##
## LEF for PtnCells ;
## created by Innovus v15.23-s045_1 on Sun Mar 16 13:41:42 2025
##

VERSION 5.8 ;

BUSBITCHARS "[]" ;
DIVIDERCHAR "/" ;

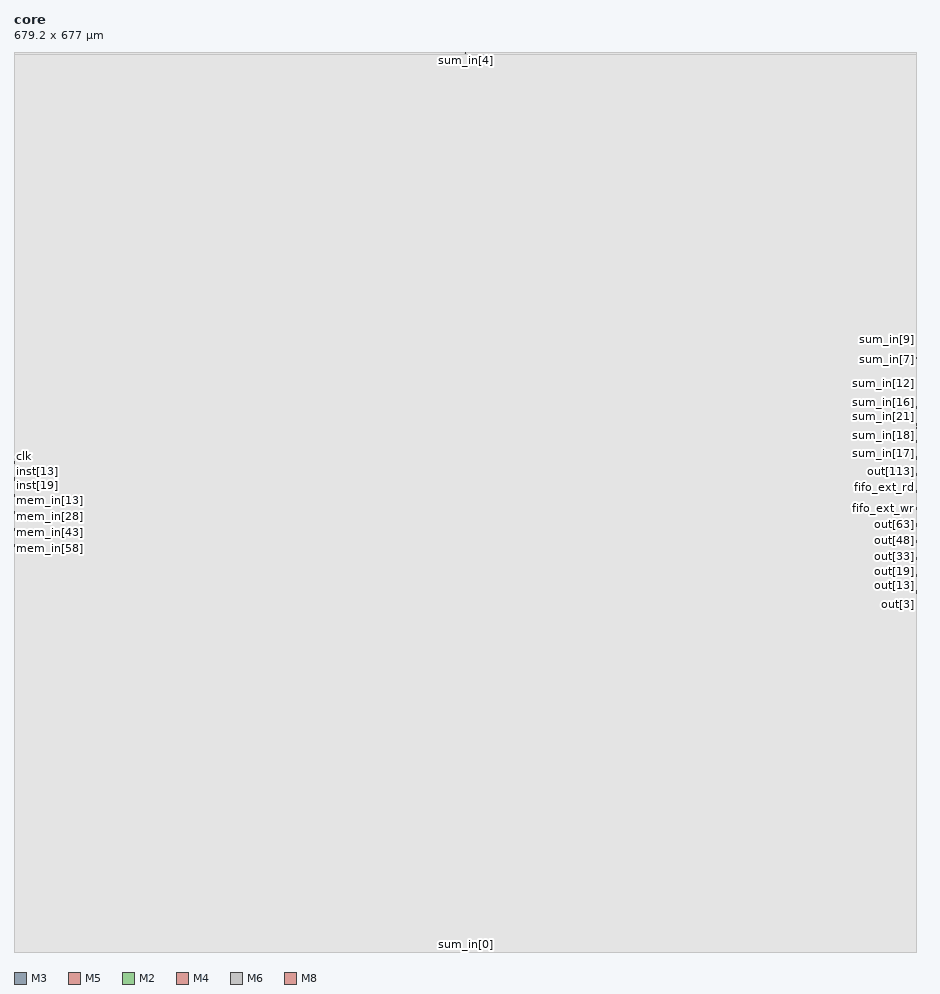
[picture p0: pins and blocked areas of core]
MACRO core
  CLASS BLOCK ;
  SIZE 679.2000 BY 677.0000 ;
  FOREIGN core 0.0000 0.0000 ;
  ORIGIN 0 0 ;
  SYMMETRY X Y R90 ;
  PIN clk
    DIRECTION INPUT ;
    USE SIGNAL ;
    PORT
      LAYER M3 ;
        RECT 0.0000 372.5500 0.6000 372.6500 ;
    END
  END clk
  PIN fifo_ext_rd
    DIRECTION OUTPUT ;
    USE SIGNAL ;
    PORT
      LAYER M5 ;
        RECT 678.6800 349.3500 679.2000 349.4500 ;
    END
  END fifo_ext_rd
  PIN fifo_ext_wr
    DIRECTION OUTPUT ;
    USE SIGNAL ;
    PORT
      LAYER M5 ;
        RECT 678.6800 339.7500 679.2000 339.8500 ;
    END
  END fifo_ext_wr
  PIN sum_in[23]
    DIRECTION INPUT ;
    USE SIGNAL ;
    PORT
      LAYER M5 ;
        RECT 678.6800 383.7500 679.2000 383.8500 ;
    END
  END sum_in[23]
  PIN sum_in[22]
    DIRECTION INPUT ;
    USE SIGNAL ;
    PORT
      LAYER M5 ;
        RECT 678.6800 401.3500 679.2000 401.4500 ;
    END
  END sum_in[22]
  PIN sum_in[21]
    DIRECTION INPUT ;
    USE SIGNAL ;
    PORT
      LAYER M5 ;
        RECT 678.6800 408.5500 679.2000 408.6500 ;
    END
  END sum_in[21]
  PIN sum_in[20]
    DIRECTION INPUT ;
    USE SIGNAL ;
    PORT
      LAYER M3 ;
        RECT 678.6800 399.9500 679.2000 400.0500 ;
    END
  END sum_in[20]
  PIN sum_in[19]
    DIRECTION INPUT ;
    USE SIGNAL ;
    PORT
      LAYER M5 ;
        RECT 678.6800 396.9500 679.2000 397.0500 ;
    END
  END sum_in[19]
  PIN sum_in[18]
    DIRECTION INPUT ;
    USE SIGNAL ;
    PORT
      LAYER M5 ;
        RECT 678.6800 394.1500 679.2000 394.2500 ;
    END
  END sum_in[18]
  PIN sum_in[17]
    DIRECTION INPUT ;
    USE SIGNAL ;
    PORT
      LAYER M3 ;
        RECT 678.6800 375.1500 679.2000 375.2500 ;
    END
  END sum_in[17]
  PIN sum_in[16]
    DIRECTION INPUT ;
    USE SIGNAL ;
    PORT
      LAYER M3 ;
        RECT 678.6800 413.3500 679.2000 413.4500 ;
    END
  END sum_in[16]
  PIN sum_in[15]
    DIRECTION INPUT ;
    USE SIGNAL ;
    PORT
      LAYER M3 ;
        RECT 678.6800 417.7500 679.2000 417.8500 ;
    END
  END sum_in[15]
  PIN sum_in[14]
    DIRECTION INPUT ;
    USE SIGNAL ;
    PORT
      LAYER M3 ;
        RECT 678.6800 433.7500 679.2000 433.8500 ;
    END
  END sum_in[14]
  PIN sum_in[13]
    DIRECTION INPUT ;
    USE SIGNAL ;
    PORT
      LAYER M3 ;
        RECT 678.6800 429.3500 679.2000 429.4500 ;
    END
  END sum_in[13]
  PIN sum_in[12]
    DIRECTION INPUT ;
    USE SIGNAL ;
    PORT
      LAYER M3 ;
        RECT 678.6800 427.5500 679.2000 427.6500 ;
    END
  END sum_in[12]
  PIN sum_in[11]
    DIRECTION INPUT ;
    USE SIGNAL ;
    PORT
      LAYER M3 ;
        RECT 678.6800 440.1500 679.2000 440.2500 ;
    END
  END sum_in[11]
  PIN sum_in[10]
    DIRECTION INPUT ;
    USE SIGNAL ;
    PORT
      LAYER M3 ;
        RECT 678.6800 446.7500 679.2000 446.8500 ;
    END
  END sum_in[10]
  PIN sum_in[9]
    DIRECTION INPUT ;
    USE SIGNAL ;
    PORT
      LAYER M3 ;
        RECT 678.6800 454.5500 679.2000 454.6500 ;
    END
  END sum_in[9]
  PIN sum_in[8]
    DIRECTION INPUT ;
    USE SIGNAL ;
    PORT
      LAYER M3 ;
        RECT 678.6800 459.1500 679.2000 459.2500 ;
    END
  END sum_in[8]
  PIN sum_in[7]
    DIRECTION INPUT ;
    USE SIGNAL ;
    PORT
      LAYER M3 ;
        RECT 678.6800 445.3500 679.2000 445.4500 ;
    END
  END sum_in[7]
  PIN sum_in[6]
    DIRECTION INPUT ;
    USE SIGNAL ;
    PORT
      LAYER M2 ;
        RECT 339.6500 676.4800 339.7500 677.0000 ;
    END
  END sum_in[6]
  PIN sum_in[5]
    DIRECTION INPUT ;
    USE SIGNAL ;
    PORT
      LAYER M4 ;
        RECT 339.6500 676.4800 339.7500 677.0000 ;
    END
  END sum_in[5]
  PIN sum_in[4]
    DIRECTION INPUT ;
    USE SIGNAL ;
    PORT
      LAYER M6 ;
        RECT 339.6500 676.4800 339.7500 677.0000 ;
    END
  END sum_in[4]
  PIN sum_in[3]
    DIRECTION INPUT ;
    USE SIGNAL ;
    PORT
      LAYER M8 ;
        RECT 339.5000 675.5850 339.9000 677.0000 ;
    END
  END sum_in[3]
  PIN sum_in[2]
    DIRECTION INPUT ;
    USE SIGNAL ;
    PORT
      LAYER M2 ;
        RECT 339.6500 0.0000 339.7500 0.5200 ;
    END
  END sum_in[2]
  PIN sum_in[1]
    DIRECTION INPUT ;
    USE SIGNAL ;
    PORT
      LAYER M4 ;
        RECT 339.6500 0.0000 339.7500 0.5200 ;
    END
  END sum_in[1]
  PIN sum_in[0]
    DIRECTION INPUT ;
    USE SIGNAL ;
    PORT
      LAYER M6 ;
        RECT 339.6500 0.0000 339.7500 0.5200 ;
    END
  END sum_in[0]
  PIN sum_out[23]
    DIRECTION OUTPUT ;
    USE SIGNAL ;
    PORT
      LAYER M3 ;
        RECT 678.6000 411.5500 679.2000 411.6500 ;
    END
  END sum_out[23]
  PIN sum_out[22]
    DIRECTION OUTPUT ;
    USE SIGNAL ;
    PORT
      LAYER M3 ;
        RECT 678.6000 410.7500 679.2000 410.8500 ;
    END
  END sum_out[22]
  PIN sum_out[21]
    DIRECTION OUTPUT ;
    USE SIGNAL ;
    PORT
      LAYER M3 ;
        RECT 678.6000 409.9500 679.2000 410.0500 ;
    END
  END sum_out[21]
  PIN sum_out[20]
    DIRECTION OUTPUT ;
    USE SIGNAL ;
    PORT
      LAYER M3 ;
        RECT 678.6000 409.1500 679.2000 409.2500 ;
    END
  END sum_out[20]
  PIN sum_out[19]
    DIRECTION OUTPUT ;
    USE SIGNAL ;
    PORT
      LAYER M3 ;
        RECT 678.6000 408.3500 679.2000 408.4500 ;
    END
  END sum_out[19]
  PIN sum_out[18]
    DIRECTION OUTPUT ;
    USE SIGNAL ;
    PORT
      LAYER M3 ;
        RECT 678.6000 407.5500 679.2000 407.6500 ;
    END
  END sum_out[18]
  PIN sum_out[17]
    DIRECTION OUTPUT ;
    USE SIGNAL ;
    PORT
      LAYER M3 ;
        RECT 678.6000 406.7500 679.2000 406.8500 ;
    END
  END sum_out[17]
  PIN sum_out[16]
    DIRECTION OUTPUT ;
    USE SIGNAL ;
    PORT
      LAYER M3 ;
        RECT 678.6000 405.9500 679.2000 406.0500 ;
    END
  END sum_out[16]
  PIN sum_out[15]
    DIRECTION OUTPUT ;
    USE SIGNAL ;
    PORT
      LAYER M3 ;
        RECT 678.6000 405.1500 679.2000 405.2500 ;
    END
  END sum_out[15]
  PIN sum_out[14]
    DIRECTION OUTPUT ;
    USE SIGNAL ;
    PORT
      LAYER M3 ;
        RECT 678.6000 404.3500 679.2000 404.4500 ;
    END
  END sum_out[14]
  PIN sum_out[13]
    DIRECTION OUTPUT ;
    USE SIGNAL ;
    PORT
      LAYER M3 ;
        RECT 678.6000 403.5500 679.2000 403.6500 ;
    END
  END sum_out[13]
  PIN sum_out[12]
    DIRECTION OUTPUT ;
    USE SIGNAL ;
    PORT
      LAYER M3 ;
        RECT 678.6000 402.7500 679.2000 402.8500 ;
    END
  END sum_out[12]
  PIN sum_out[11]
    DIRECTION OUTPUT ;
    USE SIGNAL ;
    PORT
      LAYER M3 ;
        RECT 678.6000 401.9500 679.2000 402.0500 ;
    END
  END sum_out[11]
  PIN sum_out[10]
    DIRECTION OUTPUT ;
    USE SIGNAL ;
    PORT
      LAYER M3 ;
        RECT 678.6000 401.1500 679.2000 401.2500 ;
    END
  END sum_out[10]
  PIN sum_out[9]
    DIRECTION OUTPUT ;
    USE SIGNAL ;
    PORT
      LAYER M3 ;
        RECT 678.6000 400.3500 679.2000 400.4500 ;
    END
  END sum_out[9]
  PIN sum_out[8]
    DIRECTION OUTPUT ;
    USE SIGNAL ;
    PORT
      LAYER M3 ;
        RECT 678.6000 399.5500 679.2000 399.6500 ;
    END
  END sum_out[8]
  PIN sum_out[7]
    DIRECTION OUTPUT ;
    USE SIGNAL ;
    PORT
      LAYER M3 ;
        RECT 678.6000 398.7500 679.2000 398.8500 ;
    END
  END sum_out[7]
  PIN sum_out[6]
    DIRECTION OUTPUT ;
    USE SIGNAL ;
    PORT
      LAYER M3 ;
        RECT 678.6000 397.9500 679.2000 398.0500 ;
    END
  END sum_out[6]
  PIN sum_out[5]
    DIRECTION OUTPUT ;
    USE SIGNAL ;
    PORT
      LAYER M3 ;
        RECT 678.6000 397.1500 679.2000 397.2500 ;
    END
  END sum_out[5]
  PIN sum_out[4]
    DIRECTION OUTPUT ;
    USE SIGNAL ;
    PORT
      LAYER M3 ;
        RECT 678.6000 396.3500 679.2000 396.4500 ;
    END
  END sum_out[4]
  PIN sum_out[3]
    DIRECTION OUTPUT ;
    USE SIGNAL ;
    PORT
      LAYER M3 ;
        RECT 678.6000 395.5500 679.2000 395.6500 ;
    END
  END sum_out[3]
  PIN sum_out[2]
    DIRECTION OUTPUT ;
    USE SIGNAL ;
    PORT
      LAYER M3 ;
        RECT 678.6000 394.7500 679.2000 394.8500 ;
    END
  END sum_out[2]
  PIN sum_out[1]
    DIRECTION OUTPUT ;
    USE SIGNAL ;
    PORT
      LAYER M3 ;
        RECT 678.6000 393.9500 679.2000 394.0500 ;
    END
  END sum_out[1]
  PIN sum_out[0]
    DIRECTION OUTPUT ;
    USE SIGNAL ;
    PORT
      LAYER M3 ;
        RECT 678.6000 393.1500 679.2000 393.2500 ;
    END
  END sum_out[0]
  PIN mem_in[63]
    DIRECTION INPUT ;
    USE SIGNAL ;
    PORT
      LAYER M3 ;
        RECT 0.0000 305.3500 0.6000 305.4500 ;
    END
  END mem_in[63]
  PIN mem_in[62]
    DIRECTION INPUT ;
    USE SIGNAL ;
    PORT
      LAYER M3 ;
        RECT 0.0000 306.1500 0.6000 306.2500 ;
    END
  END mem_in[62]
  PIN mem_in[61]
    DIRECTION INPUT ;
    USE SIGNAL ;
    PORT
      LAYER M3 ;
        RECT 0.0000 306.9500 0.6000 307.0500 ;
    END
  END mem_in[61]
  PIN mem_in[60]
    DIRECTION INPUT ;
    USE SIGNAL ;
    PORT
      LAYER M3 ;
        RECT 0.0000 307.7500 0.6000 307.8500 ;
    END
  END mem_in[60]
  PIN mem_in[59]
    DIRECTION INPUT ;
    USE SIGNAL ;
    PORT
      LAYER M3 ;
        RECT 0.0000 308.5500 0.6000 308.6500 ;
    END
  END mem_in[59]
  PIN mem_in[58]
    DIRECTION INPUT ;
    USE SIGNAL ;
    PORT
      LAYER M3 ;
        RECT 0.0000 309.3500 0.6000 309.4500 ;
    END
  END mem_in[58]
  PIN mem_in[57]
    DIRECTION INPUT ;
    USE SIGNAL ;
    PORT
      LAYER M3 ;
        RECT 0.0000 310.1500 0.6000 310.2500 ;
    END
  END mem_in[57]
  PIN mem_in[56]
    DIRECTION INPUT ;
    USE SIGNAL ;
    PORT
      LAYER M3 ;
        RECT 0.0000 310.9500 0.6000 311.0500 ;
    END
  END mem_in[56]
  PIN mem_in[55]
    DIRECTION INPUT ;
    USE SIGNAL ;
    PORT
      LAYER M3 ;
        RECT 0.0000 311.7500 0.6000 311.8500 ;
    END
  END mem_in[55]
  PIN mem_in[54]
    DIRECTION INPUT ;
    USE SIGNAL ;
    PORT
      LAYER M3 ;
        RECT 0.0000 312.5500 0.6000 312.6500 ;
    END
  END mem_in[54]
  PIN mem_in[53]
    DIRECTION INPUT ;
    USE SIGNAL ;
    PORT
      LAYER M3 ;
        RECT 0.0000 313.3500 0.6000 313.4500 ;
    END
  END mem_in[53]
  PIN mem_in[52]
    DIRECTION INPUT ;
    USE SIGNAL ;
    PORT
      LAYER M3 ;
        RECT 0.0000 314.1500 0.6000 314.2500 ;
    END
  END mem_in[52]
  PIN mem_in[51]
    DIRECTION INPUT ;
    USE SIGNAL ;
    PORT
      LAYER M3 ;
        RECT 0.0000 314.9500 0.6000 315.0500 ;
    END
  END mem_in[51]
  PIN mem_in[50]
    DIRECTION INPUT ;
    USE SIGNAL ;
    PORT
      LAYER M3 ;
        RECT 0.0000 315.7500 0.6000 315.8500 ;
    END
  END mem_in[50]
  PIN mem_in[49]
    DIRECTION INPUT ;
    USE SIGNAL ;
    PORT
      LAYER M3 ;
        RECT 0.0000 316.5500 0.6000 316.6500 ;
    END
  END mem_in[49]
  PIN mem_in[48]
    DIRECTION INPUT ;
    USE SIGNAL ;
    PORT
      LAYER M3 ;
        RECT 0.0000 317.3500 0.6000 317.4500 ;
    END
  END mem_in[48]
  PIN mem_in[47]
    DIRECTION INPUT ;
    USE SIGNAL ;
    PORT
      LAYER M3 ;
        RECT 0.0000 318.1500 0.6000 318.2500 ;
    END
  END mem_in[47]
  PIN mem_in[46]
    DIRECTION INPUT ;
    USE SIGNAL ;
    PORT
      LAYER M3 ;
        RECT 0.0000 318.9500 0.6000 319.0500 ;
    END
  END mem_in[46]
  PIN mem_in[45]
    DIRECTION INPUT ;
    USE SIGNAL ;
    PORT
      LAYER M3 ;
        RECT 0.0000 319.7500 0.6000 319.8500 ;
    END
  END mem_in[45]
  PIN mem_in[44]
    DIRECTION INPUT ;
    USE SIGNAL ;
    PORT
      LAYER M3 ;
        RECT 0.0000 320.5500 0.6000 320.6500 ;
    END
  END mem_in[44]
  PIN mem_in[43]
    DIRECTION INPUT ;
    USE SIGNAL ;
    PORT
      LAYER M3 ;
        RECT 0.0000 321.3500 0.6000 321.4500 ;
    END
  END mem_in[43]
  PIN mem_in[42]
    DIRECTION INPUT ;
    USE SIGNAL ;
    PORT
      LAYER M3 ;
        RECT 0.0000 322.1500 0.6000 322.2500 ;
    END
  END mem_in[42]
  PIN mem_in[41]
    DIRECTION INPUT ;
    USE SIGNAL ;
    PORT
      LAYER M3 ;
        RECT 0.0000 322.9500 0.6000 323.0500 ;
    END
  END mem_in[41]
  PIN mem_in[40]
    DIRECTION INPUT ;
    USE SIGNAL ;
    PORT
      LAYER M3 ;
        RECT 0.0000 323.7500 0.6000 323.8500 ;
    END
  END mem_in[40]
  PIN mem_in[39]
    DIRECTION INPUT ;
    USE SIGNAL ;
    PORT
      LAYER M3 ;
        RECT 0.0000 324.5500 0.6000 324.6500 ;
    END
  END mem_in[39]
  PIN mem_in[38]
    DIRECTION INPUT ;
    USE SIGNAL ;
    PORT
      LAYER M3 ;
        RECT 0.0000 325.3500 0.6000 325.4500 ;
    END
  END mem_in[38]
  PIN mem_in[37]
    DIRECTION INPUT ;
    USE SIGNAL ;
    PORT
      LAYER M3 ;
        RECT 0.0000 326.1500 0.6000 326.2500 ;
    END
  END mem_in[37]
  PIN mem_in[36]
    DIRECTION INPUT ;
    USE SIGNAL ;
    PORT
      LAYER M3 ;
        RECT 0.0000 326.9500 0.6000 327.0500 ;
    END
  END mem_in[36]
  PIN mem_in[35]
    DIRECTION INPUT ;
    USE SIGNAL ;
    PORT
      LAYER M3 ;
        RECT 0.0000 327.7500 0.6000 327.8500 ;
    END
  END mem_in[35]
  PIN mem_in[34]
    DIRECTION INPUT ;
    USE SIGNAL ;
    PORT
      LAYER M3 ;
        RECT 0.0000 328.5500 0.6000 328.6500 ;
    END
  END mem_in[34]
  PIN mem_in[33]
    DIRECTION INPUT ;
    USE SIGNAL ;
    PORT
      LAYER M3 ;
        RECT 0.0000 329.3500 0.6000 329.4500 ;
    END
  END mem_in[33]
  PIN mem_in[32]
    DIRECTION INPUT ;
    USE SIGNAL ;
    PORT
      LAYER M3 ;
        RECT 0.0000 330.1500 0.6000 330.2500 ;
    END
  END mem_in[32]
  PIN mem_in[31]
    DIRECTION INPUT ;
    USE SIGNAL ;
    PORT
      LAYER M3 ;
        RECT 0.0000 330.9500 0.6000 331.0500 ;
    END
  END mem_in[31]
  PIN mem_in[30]
    DIRECTION INPUT ;
    USE SIGNAL ;
    PORT
      LAYER M3 ;
        RECT 0.0000 331.7500 0.6000 331.8500 ;
    END
  END mem_in[30]
  PIN mem_in[29]
    DIRECTION INPUT ;
    USE SIGNAL ;
    PORT
      LAYER M3 ;
        RECT 0.0000 332.5500 0.6000 332.6500 ;
    END
  END mem_in[29]
  PIN mem_in[28]
    DIRECTION INPUT ;
    USE SIGNAL ;
    PORT
      LAYER M3 ;
        RECT 0.0000 333.3500 0.6000 333.4500 ;
    END
  END mem_in[28]
  PIN mem_in[27]
    DIRECTION INPUT ;
    USE SIGNAL ;
    PORT
      LAYER M3 ;
        RECT 0.0000 334.1500 0.6000 334.2500 ;
    END
  END mem_in[27]
  PIN mem_in[26]
    DIRECTION INPUT ;
    USE SIGNAL ;
    PORT
      LAYER M3 ;
        RECT 0.0000 334.9500 0.6000 335.0500 ;
    END
  END mem_in[26]
  PIN mem_in[25]
    DIRECTION INPUT ;
    USE SIGNAL ;
    PORT
      LAYER M3 ;
        RECT 0.0000 335.7500 0.6000 335.8500 ;
    END
  END mem_in[25]
  PIN mem_in[24]
    DIRECTION INPUT ;
    USE SIGNAL ;
    PORT
      LAYER M3 ;
        RECT 0.0000 336.5500 0.6000 336.6500 ;
    END
  END mem_in[24]
  PIN mem_in[23]
    DIRECTION INPUT ;
    USE SIGNAL ;
    PORT
      LAYER M3 ;
        RECT 0.0000 337.3500 0.6000 337.4500 ;
    END
  END mem_in[23]
  PIN mem_in[22]
    DIRECTION INPUT ;
    USE SIGNAL ;
    PORT
      LAYER M3 ;
        RECT 0.0000 338.1500 0.6000 338.2500 ;
    END
  END mem_in[22]
  PIN mem_in[21]
    DIRECTION INPUT ;
    USE SIGNAL ;
    PORT
      LAYER M3 ;
        RECT 0.0000 338.9500 0.6000 339.0500 ;
    END
  END mem_in[21]
  PIN mem_in[20]
    DIRECTION INPUT ;
    USE SIGNAL ;
    PORT
      LAYER M3 ;
        RECT 0.0000 339.7500 0.6000 339.8500 ;
    END
  END mem_in[20]
  PIN mem_in[19]
    DIRECTION INPUT ;
    USE SIGNAL ;
    PORT
      LAYER M3 ;
        RECT 0.0000 340.5500 0.6000 340.6500 ;
    END
  END mem_in[19]
  PIN mem_in[18]
    DIRECTION INPUT ;
    USE SIGNAL ;
    PORT
      LAYER M3 ;
        RECT 0.0000 341.3500 0.6000 341.4500 ;
    END
  END mem_in[18]
  PIN mem_in[17]
    DIRECTION INPUT ;
    USE SIGNAL ;
    PORT
      LAYER M3 ;
        RECT 0.0000 342.1500 0.6000 342.2500 ;
    END
  END mem_in[17]
  PIN mem_in[16]
    DIRECTION INPUT ;
    USE SIGNAL ;
    PORT
      LAYER M3 ;
        RECT 0.0000 342.9500 0.6000 343.0500 ;
    END
  END mem_in[16]
  PIN mem_in[15]
    DIRECTION INPUT ;
    USE SIGNAL ;
    PORT
      LAYER M3 ;
        RECT 0.0000 343.7500 0.6000 343.8500 ;
    END
  END mem_in[15]
  PIN mem_in[14]
    DIRECTION INPUT ;
    USE SIGNAL ;
    PORT
      LAYER M3 ;
        RECT 0.0000 344.5500 0.6000 344.6500 ;
    END
  END mem_in[14]
  PIN mem_in[13]
    DIRECTION INPUT ;
    USE SIGNAL ;
    PORT
      LAYER M3 ;
        RECT 0.0000 345.3500 0.6000 345.4500 ;
    END
  END mem_in[13]
  PIN mem_in[12]
    DIRECTION INPUT ;
    USE SIGNAL ;
    PORT
      LAYER M3 ;
        RECT 0.0000 346.1500 0.6000 346.2500 ;
    END
  END mem_in[12]
  PIN mem_in[11]
    DIRECTION INPUT ;
    USE SIGNAL ;
    PORT
      LAYER M3 ;
        RECT 0.0000 346.9500 0.6000 347.0500 ;
    END
  END mem_in[11]
  PIN mem_in[10]
    DIRECTION INPUT ;
    USE SIGNAL ;
    PORT
      LAYER M3 ;
        RECT 0.0000 347.7500 0.6000 347.8500 ;
    END
  END mem_in[10]
  PIN mem_in[9]
    DIRECTION INPUT ;
    USE SIGNAL ;
    PORT
      LAYER M3 ;
        RECT 0.0000 348.5500 0.6000 348.6500 ;
    END
  END mem_in[9]
  PIN mem_in[8]
    DIRECTION INPUT ;
    USE SIGNAL ;
    PORT
      LAYER M3 ;
        RECT 0.0000 349.3500 0.6000 349.4500 ;
    END
  END mem_in[8]
  PIN mem_in[7]
    DIRECTION INPUT ;
    USE SIGNAL ;
    PORT
      LAYER M3 ;
        RECT 0.0000 350.1500 0.6000 350.2500 ;
    END
  END mem_in[7]
  PIN mem_in[6]
    DIRECTION INPUT ;
    USE SIGNAL ;
    PORT
      LAYER M3 ;
        RECT 0.0000 350.9500 0.6000 351.0500 ;
    END
  END mem_in[6]
  PIN mem_in[5]
    DIRECTION INPUT ;
    USE SIGNAL ;
    PORT
      LAYER M3 ;
        RECT 0.0000 351.7500 0.6000 351.8500 ;
    END
  END mem_in[5]
  PIN mem_in[4]
    DIRECTION INPUT ;
    USE SIGNAL ;
    PORT
      LAYER M3 ;
        RECT 0.0000 352.5500 0.6000 352.6500 ;
    END
  END mem_in[4]
  PIN mem_in[3]
    DIRECTION INPUT ;
    USE SIGNAL ;
    PORT
      LAYER M3 ;
        RECT 0.0000 353.3500 0.6000 353.4500 ;
    END
  END mem_in[3]
  PIN mem_in[2]
    DIRECTION INPUT ;
    USE SIGNAL ;
    PORT
      LAYER M3 ;
        RECT 0.0000 354.1500 0.6000 354.2500 ;
    END
  END mem_in[2]
  PIN mem_in[1]
    DIRECTION INPUT ;
    USE SIGNAL ;
    PORT
      LAYER M3 ;
        RECT 0.0000 354.9500 0.6000 355.0500 ;
    END
  END mem_in[1]
  PIN mem_in[0]
    DIRECTION INPUT ;
    USE SIGNAL ;
    PORT
      LAYER M3 ;
        RECT 0.0000 355.7500 0.6000 355.8500 ;
    END
  END mem_in[0]
  PIN out[159]
    DIRECTION OUTPUT ;
    USE SIGNAL ;
    PORT
      LAYER M3 ;
        RECT 678.6000 392.3500 679.2000 392.4500 ;
    END
  END out[159]
  PIN out[158]
    DIRECTION OUTPUT ;
    USE SIGNAL ;
    PORT
      LAYER M3 ;
        RECT 678.6000 391.5500 679.2000 391.6500 ;
    END
  END out[158]
  PIN out[157]
    DIRECTION OUTPUT ;
    USE SIGNAL ;
    PORT
      LAYER M3 ;
        RECT 678.6000 390.7500 679.2000 390.8500 ;
    END
  END out[157]
  PIN out[156]
    DIRECTION OUTPUT ;
    USE SIGNAL ;
    PORT
      LAYER M3 ;
        RECT 678.6000 389.9500 679.2000 390.0500 ;
    END
  END out[156]
  PIN out[155]
    DIRECTION OUTPUT ;
    USE SIGNAL ;
    PORT
      LAYER M3 ;
        RECT 678.6000 389.1500 679.2000 389.2500 ;
    END
  END out[155]
  PIN out[154]
    DIRECTION OUTPUT ;
    USE SIGNAL ;
    PORT
      LAYER M3 ;
        RECT 678.6000 388.3500 679.2000 388.4500 ;
    END
  END out[154]
  PIN out[153]
    DIRECTION OUTPUT ;
    USE SIGNAL ;
    PORT
      LAYER M3 ;
        RECT 678.6000 387.5500 679.2000 387.6500 ;
    END
  END out[153]
  PIN out[152]
    DIRECTION OUTPUT ;
    USE SIGNAL ;
    PORT
      LAYER M3 ;
        RECT 678.6000 386.7500 679.2000 386.8500 ;
    END
  END out[152]
  PIN out[151]
    DIRECTION OUTPUT ;
    USE SIGNAL ;
    PORT
      LAYER M3 ;
        RECT 678.6000 385.9500 679.2000 386.0500 ;
    END
  END out[151]
  PIN out[150]
    DIRECTION OUTPUT ;
    USE SIGNAL ;
    PORT
      LAYER M3 ;
        RECT 678.6000 385.1500 679.2000 385.2500 ;
    END
  END out[150]
  PIN out[149]
    DIRECTION OUTPUT ;
    USE SIGNAL ;
    PORT
      LAYER M3 ;
        RECT 678.6000 384.3500 679.2000 384.4500 ;
    END
  END out[149]
  PIN out[148]
    DIRECTION OUTPUT ;
    USE SIGNAL ;
    PORT
      LAYER M3 ;
        RECT 678.6000 383.5500 679.2000 383.6500 ;
    END
  END out[148]
  PIN out[147]
    DIRECTION OUTPUT ;
    USE SIGNAL ;
    PORT
      LAYER M3 ;
        RECT 678.6000 382.7500 679.2000 382.8500 ;
    END
  END out[147]
  PIN out[146]
    DIRECTION OUTPUT ;
    USE SIGNAL ;
    PORT
      LAYER M3 ;
        RECT 678.6000 381.9500 679.2000 382.0500 ;
    END
  END out[146]
  PIN out[145]
    DIRECTION OUTPUT ;
    USE SIGNAL ;
    PORT
      LAYER M3 ;
        RECT 678.6000 381.1500 679.2000 381.2500 ;
    END
  END out[145]
  PIN out[144]
    DIRECTION OUTPUT ;
    USE SIGNAL ;
    PORT
      LAYER M3 ;
        RECT 678.6000 380.3500 679.2000 380.4500 ;
    END
  END out[144]
  PIN out[143]
    DIRECTION OUTPUT ;
    USE SIGNAL ;
    PORT
      LAYER M3 ;
        RECT 678.6000 379.5500 679.2000 379.6500 ;
    END
  END out[143]
  PIN out[142]
    DIRECTION OUTPUT ;
    USE SIGNAL ;
    PORT
      LAYER M3 ;
        RECT 678.6000 378.7500 679.2000 378.8500 ;
    END
  END out[142]
  PIN out[141]
    DIRECTION OUTPUT ;
    USE SIGNAL ;
    PORT
      LAYER M3 ;
        RECT 678.6000 377.9500 679.2000 378.0500 ;
    END
  END out[141]
  PIN out[140]
    DIRECTION OUTPUT ;
    USE SIGNAL ;
    PORT
      LAYER M3 ;
        RECT 678.6000 377.1500 679.2000 377.2500 ;
    END
  END out[140]
  PIN out[139]
    DIRECTION OUTPUT ;
    USE SIGNAL ;
    PORT
      LAYER M3 ;
        RECT 678.6000 376.3500 679.2000 376.4500 ;
    END
  END out[139]
  PIN out[138]
    DIRECTION OUTPUT ;
    USE SIGNAL ;
    PORT
      LAYER M3 ;
        RECT 678.6000 375.5500 679.2000 375.6500 ;
    END
  END out[138]
  PIN out[137]
    DIRECTION OUTPUT ;
    USE SIGNAL ;
    PORT
      LAYER M3 ;
        RECT 678.6000 374.7500 679.2000 374.8500 ;
    END
  END out[137]
  PIN out[136]
    DIRECTION OUTPUT ;
    USE SIGNAL ;
    PORT
      LAYER M3 ;
        RECT 678.6000 373.9500 679.2000 374.0500 ;
    END
  END out[136]
  PIN out[135]
    DIRECTION OUTPUT ;
    USE SIGNAL ;
    PORT
      LAYER M3 ;
        RECT 678.6000 373.1500 679.2000 373.2500 ;
    END
  END out[135]
  PIN out[134]
    DIRECTION OUTPUT ;
    USE SIGNAL ;
    PORT
      LAYER M3 ;
        RECT 678.6000 372.3500 679.2000 372.4500 ;
    END
  END out[134]
  PIN out[133]
    DIRECTION OUTPUT ;
    USE SIGNAL ;
    PORT
      LAYER M3 ;
        RECT 678.6000 371.5500 679.2000 371.6500 ;
    END
  END out[133]
  PIN out[132]
    DIRECTION OUTPUT ;
    USE SIGNAL ;
    PORT
      LAYER M3 ;
        RECT 678.6000 370.7500 679.2000 370.8500 ;
    END
  END out[132]
  PIN out[131]
    DIRECTION OUTPUT ;
    USE SIGNAL ;
    PORT
      LAYER M3 ;
        RECT 678.6000 369.9500 679.2000 370.0500 ;
    END
  END out[131]
  PIN out[130]
    DIRECTION OUTPUT ;
    USE SIGNAL ;
    PORT
      LAYER M3 ;
        RECT 678.6000 369.1500 679.2000 369.2500 ;
    END
  END out[130]
  PIN out[129]
    DIRECTION OUTPUT ;
    USE SIGNAL ;
    PORT
      LAYER M3 ;
        RECT 678.6000 368.3500 679.2000 368.4500 ;
    END
  END out[129]
  PIN out[128]
    DIRECTION OUTPUT ;
    USE SIGNAL ;
    PORT
      LAYER M3 ;
        RECT 678.6000 367.5500 679.2000 367.6500 ;
    END
  END out[128]
  PIN out[127]
    DIRECTION OUTPUT ;
    USE SIGNAL ;
    PORT
      LAYER M3 ;
        RECT 678.6000 366.7500 679.2000 366.8500 ;
    END
  END out[127]
  PIN out[126]
    DIRECTION OUTPUT ;
    USE SIGNAL ;
    PORT
      LAYER M3 ;
        RECT 678.6000 365.9500 679.2000 366.0500 ;
    END
  END out[126]
  PIN out[125]
    DIRECTION OUTPUT ;
    USE SIGNAL ;
    PORT
      LAYER M3 ;
        RECT 678.6000 365.1500 679.2000 365.2500 ;
    END
  END out[125]
  PIN out[124]
    DIRECTION OUTPUT ;
    USE SIGNAL ;
    PORT
      LAYER M3 ;
        RECT 678.6000 364.3500 679.2000 364.4500 ;
    END
  END out[124]
  PIN out[123]
    DIRECTION OUTPUT ;
    USE SIGNAL ;
    PORT
      LAYER M3 ;
        RECT 678.6000 363.5500 679.2000 363.6500 ;
    END
  END out[123]
  PIN out[122]
    DIRECTION OUTPUT ;
    USE SIGNAL ;
    PORT
      LAYER M3 ;
        RECT 678.6000 362.7500 679.2000 362.8500 ;
    END
  END out[122]
  PIN out[121]
    DIRECTION OUTPUT ;
    USE SIGNAL ;
    PORT
      LAYER M3 ;
        RECT 678.6000 361.9500 679.2000 362.0500 ;
    END
  END out[121]
  PIN out[120]
    DIRECTION OUTPUT ;
    USE SIGNAL ;
    PORT
      LAYER M3 ;
        RECT 678.6000 361.1500 679.2000 361.2500 ;
    END
  END out[120]
  PIN out[119]
    DIRECTION OUTPUT ;
    USE SIGNAL ;
    PORT
      LAYER M3 ;
        RECT 678.6000 360.3500 679.2000 360.4500 ;
    END
  END out[119]
  PIN out[118]
    DIRECTION OUTPUT ;
    USE SIGNAL ;
    PORT
      LAYER M3 ;
        RECT 678.6000 359.5500 679.2000 359.6500 ;
    END
  END out[118]
  PIN out[117]
    DIRECTION OUTPUT ;
    USE SIGNAL ;
    PORT
      LAYER M3 ;
        RECT 678.6000 358.7500 679.2000 358.8500 ;
    END
  END out[117]
  PIN out[116]
    DIRECTION OUTPUT ;
    USE SIGNAL ;
    PORT
      LAYER M3 ;
        RECT 678.6000 357.9500 679.2000 358.0500 ;
    END
  END out[116]
  PIN out[115]
    DIRECTION OUTPUT ;
    USE SIGNAL ;
    PORT
      LAYER M3 ;
        RECT 678.6000 357.1500 679.2000 357.2500 ;
    END
  END out[115]
  PIN out[114]
    DIRECTION OUTPUT ;
    USE SIGNAL ;
    PORT
      LAYER M3 ;
        RECT 678.6000 356.3500 679.2000 356.4500 ;
    END
  END out[114]
  PIN out[113]
    DIRECTION OUTPUT ;
    USE SIGNAL ;
    PORT
      LAYER M3 ;
        RECT 678.6000 355.5500 679.2000 355.6500 ;
    END
  END out[113]
  PIN out[112]
    DIRECTION OUTPUT ;
    USE SIGNAL ;
    PORT
      LAYER M3 ;
        RECT 678.6000 354.7500 679.2000 354.8500 ;
    END
  END out[112]
  PIN out[111]
    DIRECTION OUTPUT ;
    USE SIGNAL ;
    PORT
      LAYER M3 ;
        RECT 678.6000 353.9500 679.2000 354.0500 ;
    END
  END out[111]
  PIN out[110]
    DIRECTION OUTPUT ;
    USE SIGNAL ;
    PORT
      LAYER M3 ;
        RECT 678.6000 353.1500 679.2000 353.2500 ;
    END
  END out[110]
  PIN out[109]
    DIRECTION OUTPUT ;
    USE SIGNAL ;
    PORT
      LAYER M3 ;
        RECT 678.6000 352.3500 679.2000 352.4500 ;
    END
  END out[109]
  PIN out[108]
    DIRECTION OUTPUT ;
    USE SIGNAL ;
    PORT
      LAYER M3 ;
        RECT 678.6000 351.5500 679.2000 351.6500 ;
    END
  END out[108]
  PIN out[107]
    DIRECTION OUTPUT ;
    USE SIGNAL ;
    PORT
      LAYER M3 ;
        RECT 678.6000 350.7500 679.2000 350.8500 ;
    END
  END out[107]
  PIN out[106]
    DIRECTION OUTPUT ;
    USE SIGNAL ;
    PORT
      LAYER M3 ;
        RECT 678.6000 349.9500 679.2000 350.0500 ;
    END
  END out[106]
  PIN out[105]
    DIRECTION OUTPUT ;
    USE SIGNAL ;
    PORT
      LAYER M3 ;
        RECT 678.6000 349.1500 679.2000 349.2500 ;
    END
  END out[105]
  PIN out[104]
    DIRECTION OUTPUT ;
    USE SIGNAL ;
    PORT
      LAYER M3 ;
        RECT 678.6000 348.3500 679.2000 348.4500 ;
    END
  END out[104]
  PIN out[103]
    DIRECTION OUTPUT ;
    USE SIGNAL ;
    PORT
      LAYER M3 ;
        RECT 678.6000 347.5500 679.2000 347.6500 ;
    END
  END out[103]
  PIN out[102]
    DIRECTION OUTPUT ;
    USE SIGNAL ;
    PORT
      LAYER M3 ;
        RECT 678.6000 346.7500 679.2000 346.8500 ;
    END
  END out[102]
  PIN out[101]
    DIRECTION OUTPUT ;
    USE SIGNAL ;
    PORT
      LAYER M3 ;
        RECT 678.6000 345.9500 679.2000 346.0500 ;
    END
  END out[101]
  PIN out[100]
    DIRECTION OUTPUT ;
    USE SIGNAL ;
    PORT
      LAYER M3 ;
        RECT 678.6000 345.1500 679.2000 345.2500 ;
    END
  END out[100]
  PIN out[99]
    DIRECTION OUTPUT ;
    USE SIGNAL ;
    PORT
      LAYER M3 ;
        RECT 678.6000 344.3500 679.2000 344.4500 ;
    END
  END out[99]
  PIN out[98]
    DIRECTION OUTPUT ;
    USE SIGNAL ;
    PORT
      LAYER M3 ;
        RECT 678.6000 343.5500 679.2000 343.6500 ;
    END
  END out[98]
  PIN out[97]
    DIRECTION OUTPUT ;
    USE SIGNAL ;
    PORT
      LAYER M3 ;
        RECT 678.6000 342.7500 679.2000 342.8500 ;
    END
  END out[97]
  PIN out[96]
    DIRECTION OUTPUT ;
    USE SIGNAL ;
    PORT
      LAYER M3 ;
        RECT 678.6000 341.9500 679.2000 342.0500 ;
    END
  END out[96]
  PIN out[95]
    DIRECTION OUTPUT ;
    USE SIGNAL ;
    PORT
      LAYER M3 ;
        RECT 678.6000 341.1500 679.2000 341.2500 ;
    END
  END out[95]
  PIN out[94]
    DIRECTION OUTPUT ;
    USE SIGNAL ;
    PORT
      LAYER M3 ;
        RECT 678.6000 340.3500 679.2000 340.4500 ;
    END
  END out[94]
  PIN out[93]
    DIRECTION OUTPUT ;
    USE SIGNAL ;
    PORT
      LAYER M3 ;
        RECT 678.6000 339.5500 679.2000 339.6500 ;
    END
  END out[93]
  PIN out[92]
    DIRECTION OUTPUT ;
    USE SIGNAL ;
    PORT
      LAYER M3 ;
        RECT 678.6000 338.7500 679.2000 338.8500 ;
    END
  END out[92]
  PIN out[91]
    DIRECTION OUTPUT ;
    USE SIGNAL ;
    PORT
      LAYER M3 ;
        RECT 678.6000 337.9500 679.2000 338.0500 ;
    END
  END out[91]
  PIN out[90]
    DIRECTION OUTPUT ;
    USE SIGNAL ;
    PORT
      LAYER M3 ;
        RECT 678.6000 337.1500 679.2000 337.2500 ;
    END
  END out[90]
  PIN out[89]
    DIRECTION OUTPUT ;
    USE SIGNAL ;
    PORT
      LAYER M3 ;
        RECT 678.6000 336.3500 679.2000 336.4500 ;
    END
  END out[89]
  PIN out[88]
    DIRECTION OUTPUT ;
    USE SIGNAL ;
    PORT
      LAYER M3 ;
        RECT 678.6000 335.5500 679.2000 335.6500 ;
    END
  END out[88]
  PIN out[87]
    DIRECTION OUTPUT ;
    USE SIGNAL ;
    PORT
      LAYER M3 ;
        RECT 678.6000 334.7500 679.2000 334.8500 ;
    END
  END out[87]
  PIN out[86]
    DIRECTION OUTPUT ;
    USE SIGNAL ;
    PORT
      LAYER M3 ;
        RECT 678.6000 333.9500 679.2000 334.0500 ;
    END
  END out[86]
  PIN out[85]
    DIRECTION OUTPUT ;
    USE SIGNAL ;
    PORT
      LAYER M3 ;
        RECT 678.6000 333.1500 679.2000 333.2500 ;
    END
  END out[85]
  PIN out[84]
    DIRECTION OUTPUT ;
    USE SIGNAL ;
    PORT
      LAYER M3 ;
        RECT 678.6000 332.3500 679.2000 332.4500 ;
    END
  END out[84]
  PIN out[83]
    DIRECTION OUTPUT ;
    USE SIGNAL ;
    PORT
      LAYER M3 ;
        RECT 678.6000 331.5500 679.2000 331.6500 ;
    END
  END out[83]
  PIN out[82]
    DIRECTION OUTPUT ;
    USE SIGNAL ;
    PORT
      LAYER M3 ;
        RECT 678.6000 330.7500 679.2000 330.8500 ;
    END
  END out[82]
  PIN out[81]
    DIRECTION OUTPUT ;
    USE SIGNAL ;
    PORT
      LAYER M3 ;
        RECT 678.6000 329.9500 679.2000 330.0500 ;
    END
  END out[81]
  PIN out[80]
    DIRECTION OUTPUT ;
    USE SIGNAL ;
    PORT
      LAYER M3 ;
        RECT 678.6000 329.1500 679.2000 329.2500 ;
    END
  END out[80]
  PIN out[79]
    DIRECTION OUTPUT ;
    USE SIGNAL ;
    PORT
      LAYER M3 ;
        RECT 678.6000 328.3500 679.2000 328.4500 ;
    END
  END out[79]
  PIN out[78]
    DIRECTION OUTPUT ;
    USE SIGNAL ;
    PORT
      LAYER M3 ;
        RECT 678.6000 327.5500 679.2000 327.6500 ;
    END
  END out[78]
  PIN out[77]
    DIRECTION OUTPUT ;
    USE SIGNAL ;
    PORT
      LAYER M3 ;
        RECT 678.6000 326.7500 679.2000 326.8500 ;
    END
  END out[77]
  PIN out[76]
    DIRECTION OUTPUT ;
    USE SIGNAL ;
    PORT
      LAYER M3 ;
        RECT 678.6000 325.9500 679.2000 326.0500 ;
    END
  END out[76]
  PIN out[75]
    DIRECTION OUTPUT ;
    USE SIGNAL ;
    PORT
      LAYER M3 ;
        RECT 678.6000 325.1500 679.2000 325.2500 ;
    END
  END out[75]
  PIN out[74]
    DIRECTION OUTPUT ;
    USE SIGNAL ;
    PORT
      LAYER M3 ;
        RECT 678.6000 324.3500 679.2000 324.4500 ;
    END
  END out[74]
  PIN out[73]
    DIRECTION OUTPUT ;
    USE SIGNAL ;
    PORT
      LAYER M3 ;
        RECT 678.6000 323.5500 679.2000 323.6500 ;
    END
  END out[73]
  PIN out[72]
    DIRECTION OUTPUT ;
    USE SIGNAL ;
    PORT
      LAYER M3 ;
        RECT 678.6000 322.7500 679.2000 322.8500 ;
    END
  END out[72]
  PIN out[71]
    DIRECTION OUTPUT ;
    USE SIGNAL ;
    PORT
      LAYER M3 ;
        RECT 678.6000 321.9500 679.2000 322.0500 ;
    END
  END out[71]
  PIN out[70]
    DIRECTION OUTPUT ;
    USE SIGNAL ;
    PORT
      LAYER M3 ;
        RECT 678.6000 321.1500 679.2000 321.2500 ;
    END
  END out[70]
  PIN out[69]
    DIRECTION OUTPUT ;
    USE SIGNAL ;
    PORT
      LAYER M3 ;
        RECT 678.6000 320.3500 679.2000 320.4500 ;
    END
  END out[69]
  PIN out[68]
    DIRECTION OUTPUT ;
    USE SIGNAL ;
    PORT
      LAYER M3 ;
        RECT 678.6000 319.5500 679.2000 319.6500 ;
    END
  END out[68]
  PIN out[67]
    DIRECTION OUTPUT ;
    USE SIGNAL ;
    PORT
      LAYER M3 ;
        RECT 678.6000 318.7500 679.2000 318.8500 ;
    END
  END out[67]
  PIN out[66]
    DIRECTION OUTPUT ;
    USE SIGNAL ;
    PORT
      LAYER M3 ;
        RECT 678.6000 317.9500 679.2000 318.0500 ;
    END
  END out[66]
  PIN out[65]
    DIRECTION OUTPUT ;
    USE SIGNAL ;
    PORT
      LAYER M3 ;
        RECT 678.6000 317.1500 679.2000 317.2500 ;
    END
  END out[65]
  PIN out[64]
    DIRECTION OUTPUT ;
    USE SIGNAL ;
    PORT
      LAYER M3 ;
        RECT 678.6000 316.3500 679.2000 316.4500 ;
    END
  END out[64]
  PIN out[63]
    DIRECTION OUTPUT ;
    USE SIGNAL ;
    PORT
      LAYER M3 ;
        RECT 678.6000 315.5500 679.2000 315.6500 ;
    END
  END out[63]
  PIN out[62]
    DIRECTION OUTPUT ;
    USE SIGNAL ;
    PORT
      LAYER M3 ;
        RECT 678.6000 314.7500 679.2000 314.8500 ;
    END
  END out[62]
  PIN out[61]
    DIRECTION OUTPUT ;
    USE SIGNAL ;
    PORT
      LAYER M3 ;
        RECT 678.6000 313.9500 679.2000 314.0500 ;
    END
  END out[61]
  PIN out[60]
    DIRECTION OUTPUT ;
    USE SIGNAL ;
    PORT
      LAYER M3 ;
        RECT 678.6000 313.1500 679.2000 313.2500 ;
    END
  END out[60]
  PIN out[59]
    DIRECTION OUTPUT ;
    USE SIGNAL ;
    PORT
      LAYER M3 ;
        RECT 678.6000 312.3500 679.2000 312.4500 ;
    END
  END out[59]
  PIN out[58]
    DIRECTION OUTPUT ;
    USE SIGNAL ;
    PORT
      LAYER M3 ;
        RECT 678.6000 311.5500 679.2000 311.6500 ;
    END
  END out[58]
  PIN out[57]
    DIRECTION OUTPUT ;
    USE SIGNAL ;
    PORT
      LAYER M3 ;
        RECT 678.6000 310.7500 679.2000 310.8500 ;
    END
  END out[57]
  PIN out[56]
    DIRECTION OUTPUT ;
    USE SIGNAL ;
    PORT
      LAYER M3 ;
        RECT 678.6000 309.9500 679.2000 310.0500 ;
    END
  END out[56]
  PIN out[55]
    DIRECTION OUTPUT ;
    USE SIGNAL ;
    PORT
      LAYER M3 ;
        RECT 678.6000 309.1500 679.2000 309.2500 ;
    END
  END out[55]
  PIN out[54]
    DIRECTION OUTPUT ;
    USE SIGNAL ;
    PORT
      LAYER M3 ;
        RECT 678.6000 308.3500 679.2000 308.4500 ;
    END
  END out[54]
  PIN out[53]
    DIRECTION OUTPUT ;
    USE SIGNAL ;
    PORT
      LAYER M3 ;
        RECT 678.6000 307.5500 679.2000 307.6500 ;
    END
  END out[53]
  PIN out[52]
    DIRECTION OUTPUT ;
    USE SIGNAL ;
    PORT
      LAYER M3 ;
        RECT 678.6000 306.7500 679.2000 306.8500 ;
    END
  END out[52]
  PIN out[51]
    DIRECTION OUTPUT ;
    USE SIGNAL ;
    PORT
      LAYER M3 ;
        RECT 678.6000 305.9500 679.2000 306.0500 ;
    END
  END out[51]
  PIN out[50]
    DIRECTION OUTPUT ;
    USE SIGNAL ;
    PORT
      LAYER M3 ;
        RECT 678.6000 305.1500 679.2000 305.2500 ;
    END
  END out[50]
  PIN out[49]
    DIRECTION OUTPUT ;
    USE SIGNAL ;
    PORT
      LAYER M3 ;
        RECT 678.6000 304.3500 679.2000 304.4500 ;
    END
  END out[49]
  PIN out[48]
    DIRECTION OUTPUT ;
    USE SIGNAL ;
    PORT
      LAYER M3 ;
        RECT 678.6000 303.5500 679.2000 303.6500 ;
    END
  END out[48]
  PIN out[47]
    DIRECTION OUTPUT ;
    USE SIGNAL ;
    PORT
      LAYER M3 ;
        RECT 678.6000 302.7500 679.2000 302.8500 ;
    END
  END out[47]
  PIN out[46]
    DIRECTION OUTPUT ;
    USE SIGNAL ;
    PORT
      LAYER M3 ;
        RECT 678.6000 301.9500 679.2000 302.0500 ;
    END
  END out[46]
  PIN out[45]
    DIRECTION OUTPUT ;
    USE SIGNAL ;
    PORT
      LAYER M3 ;
        RECT 678.6000 301.1500 679.2000 301.2500 ;
    END
  END out[45]
  PIN out[44]
    DIRECTION OUTPUT ;
    USE SIGNAL ;
    PORT
      LAYER M3 ;
        RECT 678.6000 300.3500 679.2000 300.4500 ;
    END
  END out[44]
  PIN out[43]
    DIRECTION OUTPUT ;
    USE SIGNAL ;
    PORT
      LAYER M3 ;
        RECT 678.6000 299.5500 679.2000 299.6500 ;
    END
  END out[43]
  PIN out[42]
    DIRECTION OUTPUT ;
    USE SIGNAL ;
    PORT
      LAYER M3 ;
        RECT 678.6000 298.7500 679.2000 298.8500 ;
    END
  END out[42]
  PIN out[41]
    DIRECTION OUTPUT ;
    USE SIGNAL ;
    PORT
      LAYER M3 ;
        RECT 678.6000 297.9500 679.2000 298.0500 ;
    END
  END out[41]
  PIN out[40]
    DIRECTION OUTPUT ;
    USE SIGNAL ;
    PORT
      LAYER M3 ;
        RECT 678.6000 297.1500 679.2000 297.2500 ;
    END
  END out[40]
  PIN out[39]
    DIRECTION OUTPUT ;
    USE SIGNAL ;
    PORT
      LAYER M3 ;
        RECT 678.6000 296.3500 679.2000 296.4500 ;
    END
  END out[39]
  PIN out[38]
    DIRECTION OUTPUT ;
    USE SIGNAL ;
    PORT
      LAYER M3 ;
        RECT 678.6000 295.5500 679.2000 295.6500 ;
    END
  END out[38]
  PIN out[37]
    DIRECTION OUTPUT ;
    USE SIGNAL ;
    PORT
      LAYER M3 ;
        RECT 678.6000 294.7500 679.2000 294.8500 ;
    END
  END out[37]
  PIN out[36]
    DIRECTION OUTPUT ;
    USE SIGNAL ;
    PORT
      LAYER M3 ;
        RECT 678.6000 293.9500 679.2000 294.0500 ;
    END
  END out[36]
  PIN out[35]
    DIRECTION OUTPUT ;
    USE SIGNAL ;
    PORT
      LAYER M3 ;
        RECT 678.6000 293.1500 679.2000 293.2500 ;
    END
  END out[35]
  PIN out[34]
    DIRECTION OUTPUT ;
    USE SIGNAL ;
    PORT
      LAYER M3 ;
        RECT 678.6000 292.3500 679.2000 292.4500 ;
    END
  END out[34]
  PIN out[33]
    DIRECTION OUTPUT ;
    USE SIGNAL ;
    PORT
      LAYER M3 ;
        RECT 678.6000 291.5500 679.2000 291.6500 ;
    END
  END out[33]
  PIN out[32]
    DIRECTION OUTPUT ;
    USE SIGNAL ;
    PORT
      LAYER M3 ;
        RECT 678.6000 290.7500 679.2000 290.8500 ;
    END
  END out[32]
  PIN out[31]
    DIRECTION OUTPUT ;
    USE SIGNAL ;
    PORT
      LAYER M3 ;
        RECT 678.6000 289.9500 679.2000 290.0500 ;
    END
  END out[31]
  PIN out[30]
    DIRECTION OUTPUT ;
    USE SIGNAL ;
    PORT
      LAYER M3 ;
        RECT 678.6000 289.1500 679.2000 289.2500 ;
    END
  END out[30]
  PIN out[29]
    DIRECTION OUTPUT ;
    USE SIGNAL ;
    PORT
      LAYER M3 ;
        RECT 678.6000 288.3500 679.2000 288.4500 ;
    END
  END out[29]
  PIN out[28]
    DIRECTION OUTPUT ;
    USE SIGNAL ;
    PORT
      LAYER M3 ;
        RECT 678.6000 287.5500 679.2000 287.6500 ;
    END
  END out[28]
  PIN out[27]
    DIRECTION OUTPUT ;
    USE SIGNAL ;
    PORT
      LAYER M3 ;
        RECT 678.6000 286.7500 679.2000 286.8500 ;
    END
  END out[27]
  PIN out[26]
    DIRECTION OUTPUT ;
    USE SIGNAL ;
    PORT
      LAYER M3 ;
        RECT 678.6000 285.9500 679.2000 286.0500 ;
    END
  END out[26]
  PIN out[25]
    DIRECTION OUTPUT ;
    USE SIGNAL ;
    PORT
      LAYER M3 ;
        RECT 678.6000 285.1500 679.2000 285.2500 ;
    END
  END out[25]
  PIN out[24]
    DIRECTION OUTPUT ;
    USE SIGNAL ;
    PORT
      LAYER M3 ;
        RECT 678.6000 284.3500 679.2000 284.4500 ;
    END
  END out[24]
  PIN out[23]
    DIRECTION OUTPUT ;
    USE SIGNAL ;
    PORT
      LAYER M3 ;
        RECT 678.6000 283.5500 679.2000 283.6500 ;
    END
  END out[23]
  PIN out[22]
    DIRECTION OUTPUT ;
    USE SIGNAL ;
    PORT
      LAYER M3 ;
        RECT 678.6000 282.7500 679.2000 282.8500 ;
    END
  END out[22]
  PIN out[21]
    DIRECTION OUTPUT ;
    USE SIGNAL ;
    PORT
      LAYER M3 ;
        RECT 678.6000 281.9500 679.2000 282.0500 ;
    END
  END out[21]
  PIN out[20]
    DIRECTION OUTPUT ;
    USE SIGNAL ;
    PORT
      LAYER M3 ;
        RECT 678.6000 281.1500 679.2000 281.2500 ;
    END
  END out[20]
  PIN out[19]
    DIRECTION OUTPUT ;
    USE SIGNAL ;
    PORT
      LAYER M3 ;
        RECT 678.6000 280.3500 679.2000 280.4500 ;
    END
  END out[19]
  PIN out[18]
    DIRECTION OUTPUT ;
    USE SIGNAL ;
    PORT
      LAYER M3 ;
        RECT 678.6000 279.5500 679.2000 279.6500 ;
    END
  END out[18]
  PIN out[17]
    DIRECTION OUTPUT ;
    USE SIGNAL ;
    PORT
      LAYER M3 ;
        RECT 678.6000 278.7500 679.2000 278.8500 ;
    END
  END out[17]
  PIN out[16]
    DIRECTION OUTPUT ;
    USE SIGNAL ;
    PORT
      LAYER M3 ;
        RECT 678.6000 277.9500 679.2000 278.0500 ;
    END
  END out[16]
  PIN out[15]
    DIRECTION OUTPUT ;
    USE SIGNAL ;
    PORT
      LAYER M3 ;
        RECT 678.6000 277.1500 679.2000 277.2500 ;
    END
  END out[15]
  PIN out[14]
    DIRECTION OUTPUT ;
    USE SIGNAL ;
    PORT
      LAYER M3 ;
        RECT 678.6000 276.3500 679.2000 276.4500 ;
    END
  END out[14]
  PIN out[13]
    DIRECTION OUTPUT ;
    USE SIGNAL ;
    PORT
      LAYER M3 ;
        RECT 678.6000 275.5500 679.2000 275.6500 ;
    END
  END out[13]
  PIN out[12]
    DIRECTION OUTPUT ;
    USE SIGNAL ;
    PORT
      LAYER M3 ;
        RECT 678.6000 274.7500 679.2000 274.8500 ;
    END
  END out[12]
  PIN out[11]
    DIRECTION OUTPUT ;
    USE SIGNAL ;
    PORT
      LAYER M3 ;
        RECT 678.6000 273.9500 679.2000 274.0500 ;
    END
  END out[11]
  PIN out[10]
    DIRECTION OUTPUT ;
    USE SIGNAL ;
    PORT
      LAYER M3 ;
        RECT 678.6000 273.1500 679.2000 273.2500 ;
    END
  END out[10]
  PIN out[9]
    DIRECTION OUTPUT ;
    USE SIGNAL ;
    PORT
      LAYER M3 ;
        RECT 678.6000 272.3500 679.2000 272.4500 ;
    END
  END out[9]
  PIN out[8]
    DIRECTION OUTPUT ;
    USE SIGNAL ;
    PORT
      LAYER M3 ;
        RECT 678.6000 271.5500 679.2000 271.6500 ;
    END
  END out[8]
  PIN out[7]
    DIRECTION OUTPUT ;
    USE SIGNAL ;
    PORT
      LAYER M3 ;
        RECT 678.6000 270.7500 679.2000 270.8500 ;
    END
  END out[7]
  PIN out[6]
    DIRECTION OUTPUT ;
    USE SIGNAL ;
    PORT
      LAYER M3 ;
        RECT 678.6000 269.9500 679.2000 270.0500 ;
    END
  END out[6]
  PIN out[5]
    DIRECTION OUTPUT ;
    USE SIGNAL ;
    PORT
      LAYER M3 ;
        RECT 678.6000 269.1500 679.2000 269.2500 ;
    END
  END out[5]
  PIN out[4]
    DIRECTION OUTPUT ;
    USE SIGNAL ;
    PORT
      LAYER M3 ;
        RECT 678.6000 268.3500 679.2000 268.4500 ;
    END
  END out[4]
  PIN out[3]
    DIRECTION OUTPUT ;
    USE SIGNAL ;
    PORT
      LAYER M3 ;
        RECT 678.6000 267.5500 679.2000 267.6500 ;
    END
  END out[3]
  PIN out[2]
    DIRECTION OUTPUT ;
    USE SIGNAL ;
    PORT
      LAYER M3 ;
        RECT 678.6000 266.7500 679.2000 266.8500 ;
    END
  END out[2]
  PIN out[1]
    DIRECTION OUTPUT ;
    USE SIGNAL ;
    PORT
      LAYER M3 ;
        RECT 678.6000 265.9500 679.2000 266.0500 ;
    END
  END out[1]
  PIN out[0]
    DIRECTION OUTPUT ;
    USE SIGNAL ;
    PORT
      LAYER M3 ;
        RECT 678.6000 265.1500 679.2000 265.2500 ;
    END
  END out[0]
  PIN inst[19]
    DIRECTION INPUT ;
    USE SIGNAL ;
    PORT
      LAYER M3 ;
        RECT 0.0000 356.5500 0.6000 356.6500 ;
    END
  END inst[19]
  PIN inst[18]
    DIRECTION INPUT ;
    USE SIGNAL ;
    PORT
      LAYER M3 ;
        RECT 0.0000 357.3500 0.6000 357.4500 ;
    END
  END inst[18]
  PIN inst[17]
    DIRECTION INPUT ;
    USE SIGNAL ;
    PORT
      LAYER M3 ;
        RECT 0.0000 358.1500 0.6000 358.2500 ;
    END
  END inst[17]
  PIN inst[16]
    DIRECTION INPUT ;
    USE SIGNAL ;
    PORT
      LAYER M3 ;
        RECT 0.0000 358.9500 0.6000 359.0500 ;
    END
  END inst[16]
  PIN inst[15]
    DIRECTION INPUT ;
    USE SIGNAL ;
    PORT
      LAYER M3 ;
        RECT 0.0000 359.7500 0.6000 359.8500 ;
    END
  END inst[15]
  PIN inst[14]
    DIRECTION INPUT ;
    USE SIGNAL ;
    PORT
      LAYER M3 ;
        RECT 0.0000 360.5500 0.6000 360.6500 ;
    END
  END inst[14]
  PIN inst[13]
    DIRECTION INPUT ;
    USE SIGNAL ;
    PORT
      LAYER M3 ;
        RECT 0.0000 361.3500 0.6000 361.4500 ;
    END
  END inst[13]
  PIN inst[12]
    DIRECTION INPUT ;
    USE SIGNAL ;
    PORT
      LAYER M3 ;
        RECT 0.0000 362.1500 0.6000 362.2500 ;
    END
  END inst[12]
  PIN inst[11]
    DIRECTION INPUT ;
    USE SIGNAL ;
    PORT
      LAYER M3 ;
        RECT 0.0000 362.9500 0.6000 363.0500 ;
    END
  END inst[11]
  PIN inst[10]
    DIRECTION INPUT ;
    USE SIGNAL ;
    PORT
      LAYER M3 ;
        RECT 0.0000 363.7500 0.6000 363.8500 ;
    END
  END inst[10]
  PIN inst[9]
    DIRECTION INPUT ;
    USE SIGNAL ;
    PORT
      LAYER M3 ;
        RECT 0.0000 364.5500 0.6000 364.6500 ;
    END
  END inst[9]
  PIN inst[8]
    DIRECTION INPUT ;
    USE SIGNAL ;
    PORT
      LAYER M3 ;
        RECT 0.0000 365.3500 0.6000 365.4500 ;
    END
  END inst[8]
  PIN inst[7]
    DIRECTION INPUT ;
    USE SIGNAL ;
    PORT
      LAYER M3 ;
        RECT 0.0000 366.1500 0.6000 366.2500 ;
    END
  END inst[7]
  PIN inst[6]
    DIRECTION INPUT ;
    USE SIGNAL ;
    PORT
      LAYER M3 ;
        RECT 0.0000 366.9500 0.6000 367.0500 ;
    END
  END inst[6]
  PIN inst[5]
    DIRECTION INPUT ;
    USE SIGNAL ;
    PORT
      LAYER M3 ;
        RECT 0.0000 367.7500 0.6000 367.8500 ;
    END
  END inst[5]
  PIN inst[4]
    DIRECTION INPUT ;
    USE SIGNAL ;
    PORT
      LAYER M3 ;
        RECT 0.0000 368.5500 0.6000 368.6500 ;
    END
  END inst[4]
  PIN inst[3]
    DIRECTION INPUT ;
    USE SIGNAL ;
    PORT
      LAYER M3 ;
        RECT 0.0000 369.3500 0.6000 369.4500 ;
    END
  END inst[3]
  PIN inst[2]
    DIRECTION INPUT ;
    USE SIGNAL ;
    PORT
      LAYER M3 ;
        RECT 0.0000 370.1500 0.6000 370.2500 ;
    END
  END inst[2]
  PIN inst[1]
    DIRECTION INPUT ;
    USE SIGNAL ;
    PORT
      LAYER M3 ;
        RECT 0.0000 370.9500 0.6000 371.0500 ;
    END
  END inst[1]
  PIN inst[0]
    DIRECTION INPUT ;
    USE SIGNAL ;
    PORT
      LAYER M3 ;
        RECT 0.0000 371.7500 0.6000 371.8500 ;
    END
  END inst[0]
  PIN reset
    DIRECTION INPUT ;
    USE SIGNAL ;
    PORT
      LAYER M3 ;
        RECT 0.0000 304.5500 0.6000 304.6500 ;
    END
  END reset
  OBS
    LAYER M1 ;
      RECT 0.0000 0.0000 679.2000 677.0000 ;
    LAYER M2 ;
      RECT 339.8500 676.3800 679.2000 677.0000 ;
      RECT 0.0000 676.3800 339.5500 677.0000 ;
      RECT 0.0000 0.6200 679.2000 676.3800 ;
      RECT 339.8500 0.0000 679.2000 0.6200 ;
      RECT 0.0000 0.0000 339.5500 0.6200 ;
    LAYER M3 ;
      RECT 0.0000 459.3500 679.2000 677.0000 ;
      RECT 0.0000 459.0500 678.5800 459.3500 ;
      RECT 0.0000 454.7500 679.2000 459.0500 ;
      RECT 0.0000 454.4500 678.5800 454.7500 ;
      RECT 0.0000 446.9500 679.2000 454.4500 ;
      RECT 0.0000 446.6500 678.5800 446.9500 ;
      RECT 0.0000 445.5500 679.2000 446.6500 ;
      RECT 0.0000 445.2500 678.5800 445.5500 ;
      RECT 0.0000 440.3500 679.2000 445.2500 ;
      RECT 0.0000 440.0500 678.5800 440.3500 ;
      RECT 0.0000 433.9500 679.2000 440.0500 ;
      RECT 0.0000 433.6500 678.5800 433.9500 ;
      RECT 0.0000 429.5500 679.2000 433.6500 ;
      RECT 0.0000 429.2500 678.5800 429.5500 ;
      RECT 0.0000 427.7500 679.2000 429.2500 ;
      RECT 0.0000 427.4500 678.5800 427.7500 ;
      RECT 0.0000 417.9500 679.2000 427.4500 ;
      RECT 0.0000 417.6500 678.5800 417.9500 ;
      RECT 0.0000 413.5500 679.2000 417.6500 ;
      RECT 0.0000 413.2500 678.5800 413.5500 ;
      RECT 0.0000 411.7500 679.2000 413.2500 ;
      RECT 0.0000 411.4500 678.5000 411.7500 ;
      RECT 0.0000 410.9500 679.2000 411.4500 ;
      RECT 0.0000 410.6500 678.5000 410.9500 ;
      RECT 0.0000 410.1500 679.2000 410.6500 ;
      RECT 0.0000 409.8500 678.5000 410.1500 ;
      RECT 0.0000 409.3500 679.2000 409.8500 ;
      RECT 0.0000 409.0500 678.5000 409.3500 ;
      RECT 0.0000 408.5500 679.2000 409.0500 ;
      RECT 0.0000 408.2500 678.5000 408.5500 ;
      RECT 0.0000 407.7500 679.2000 408.2500 ;
      RECT 0.0000 407.4500 678.5000 407.7500 ;
      RECT 0.0000 406.9500 679.2000 407.4500 ;
      RECT 0.0000 406.6500 678.5000 406.9500 ;
      RECT 0.0000 406.1500 679.2000 406.6500 ;
      RECT 0.0000 405.8500 678.5000 406.1500 ;
      RECT 0.0000 405.3500 679.2000 405.8500 ;
      RECT 0.0000 405.0500 678.5000 405.3500 ;
      RECT 0.0000 404.5500 679.2000 405.0500 ;
      RECT 0.0000 404.2500 678.5000 404.5500 ;
      RECT 0.0000 403.7500 679.2000 404.2500 ;
      RECT 0.0000 403.4500 678.5000 403.7500 ;
      RECT 0.0000 402.9500 679.2000 403.4500 ;
      RECT 0.0000 402.6500 678.5000 402.9500 ;
      RECT 0.0000 402.1500 679.2000 402.6500 ;
      RECT 0.0000 401.8500 678.5000 402.1500 ;
      RECT 0.0000 401.3500 679.2000 401.8500 ;
      RECT 0.0000 401.0500 678.5000 401.3500 ;
      RECT 0.0000 400.5500 679.2000 401.0500 ;
      RECT 0.0000 400.2500 678.5000 400.5500 ;
      RECT 0.0000 400.1500 679.2000 400.2500 ;
      RECT 0.0000 399.8500 678.5800 400.1500 ;
      RECT 0.0000 399.7500 679.2000 399.8500 ;
      RECT 0.0000 399.4500 678.5000 399.7500 ;
      RECT 0.0000 398.9500 679.2000 399.4500 ;
      RECT 0.0000 398.6500 678.5000 398.9500 ;
      RECT 0.0000 398.1500 679.2000 398.6500 ;
      RECT 0.0000 397.8500 678.5000 398.1500 ;
      RECT 0.0000 397.3500 679.2000 397.8500 ;
      RECT 0.0000 397.0500 678.5000 397.3500 ;
      RECT 0.0000 396.5500 679.2000 397.0500 ;
      RECT 0.0000 396.2500 678.5000 396.5500 ;
      RECT 0.0000 395.7500 679.2000 396.2500 ;
      RECT 0.0000 395.4500 678.5000 395.7500 ;
      RECT 0.0000 394.9500 679.2000 395.4500 ;
      RECT 0.0000 394.6500 678.5000 394.9500 ;
      RECT 0.0000 394.1500 679.2000 394.6500 ;
      RECT 0.0000 393.8500 678.5000 394.1500 ;
      RECT 0.0000 393.3500 679.2000 393.8500 ;
      RECT 0.0000 393.0500 678.5000 393.3500 ;
      RECT 0.0000 392.5500 679.2000 393.0500 ;
      RECT 0.0000 392.2500 678.5000 392.5500 ;
      RECT 0.0000 391.7500 679.2000 392.2500 ;
      RECT 0.0000 391.4500 678.5000 391.7500 ;
      RECT 0.0000 390.9500 679.2000 391.4500 ;
      RECT 0.0000 390.6500 678.5000 390.9500 ;
      RECT 0.0000 390.1500 679.2000 390.6500 ;
      RECT 0.0000 389.8500 678.5000 390.1500 ;
      RECT 0.0000 389.3500 679.2000 389.8500 ;
      RECT 0.0000 389.0500 678.5000 389.3500 ;
      RECT 0.0000 388.5500 679.2000 389.0500 ;
      RECT 0.0000 388.2500 678.5000 388.5500 ;
      RECT 0.0000 387.7500 679.2000 388.2500 ;
      RECT 0.0000 387.4500 678.5000 387.7500 ;
      RECT 0.0000 386.9500 679.2000 387.4500 ;
      RECT 0.0000 386.6500 678.5000 386.9500 ;
      RECT 0.0000 386.1500 679.2000 386.6500 ;
      RECT 0.0000 385.8500 678.5000 386.1500 ;
      RECT 0.0000 385.3500 679.2000 385.8500 ;
      RECT 0.0000 385.0500 678.5000 385.3500 ;
      RECT 0.0000 384.5500 679.2000 385.0500 ;
      RECT 0.0000 384.2500 678.5000 384.5500 ;
      RECT 0.0000 383.7500 679.2000 384.2500 ;
      RECT 0.0000 383.4500 678.5000 383.7500 ;
      RECT 0.0000 382.9500 679.2000 383.4500 ;
      RECT 0.0000 382.6500 678.5000 382.9500 ;
      RECT 0.0000 382.1500 679.2000 382.6500 ;
      RECT 0.0000 381.8500 678.5000 382.1500 ;
      RECT 0.0000 381.3500 679.2000 381.8500 ;
      RECT 0.0000 381.0500 678.5000 381.3500 ;
      RECT 0.0000 380.5500 679.2000 381.0500 ;
      RECT 0.0000 380.2500 678.5000 380.5500 ;
      RECT 0.0000 379.7500 679.2000 380.2500 ;
      RECT 0.0000 379.4500 678.5000 379.7500 ;
      RECT 0.0000 378.9500 679.2000 379.4500 ;
      RECT 0.0000 378.6500 678.5000 378.9500 ;
      RECT 0.0000 378.1500 679.2000 378.6500 ;
      RECT 0.0000 377.8500 678.5000 378.1500 ;
      RECT 0.0000 377.3500 679.2000 377.8500 ;
      RECT 0.0000 377.0500 678.5000 377.3500 ;
      RECT 0.0000 376.5500 679.2000 377.0500 ;
      RECT 0.0000 376.2500 678.5000 376.5500 ;
      RECT 0.0000 375.7500 679.2000 376.2500 ;
      RECT 0.0000 375.4500 678.5000 375.7500 ;
      RECT 0.0000 375.3500 679.2000 375.4500 ;
      RECT 0.0000 375.0500 678.5800 375.3500 ;
      RECT 0.0000 374.9500 679.2000 375.0500 ;
      RECT 0.0000 374.6500 678.5000 374.9500 ;
      RECT 0.0000 374.1500 679.2000 374.6500 ;
      RECT 0.0000 373.8500 678.5000 374.1500 ;
      RECT 0.0000 373.3500 679.2000 373.8500 ;
      RECT 0.0000 373.0500 678.5000 373.3500 ;
      RECT 0.0000 372.7500 679.2000 373.0500 ;
      RECT 0.7000 372.5500 679.2000 372.7500 ;
      RECT 0.7000 372.4500 678.5000 372.5500 ;
      RECT 0.0000 372.2500 678.5000 372.4500 ;
      RECT 0.0000 371.9500 679.2000 372.2500 ;
      RECT 0.7000 371.7500 679.2000 371.9500 ;
      RECT 0.7000 371.6500 678.5000 371.7500 ;
      RECT 0.0000 371.4500 678.5000 371.6500 ;
      RECT 0.0000 371.1500 679.2000 371.4500 ;
      RECT 0.7000 370.9500 679.2000 371.1500 ;
      RECT 0.7000 370.8500 678.5000 370.9500 ;
      RECT 0.0000 370.6500 678.5000 370.8500 ;
      RECT 0.0000 370.3500 679.2000 370.6500 ;
      RECT 0.7000 370.1500 679.2000 370.3500 ;
      RECT 0.7000 370.0500 678.5000 370.1500 ;
      RECT 0.0000 369.8500 678.5000 370.0500 ;
      RECT 0.0000 369.5500 679.2000 369.8500 ;
      RECT 0.7000 369.3500 679.2000 369.5500 ;
      RECT 0.7000 369.2500 678.5000 369.3500 ;
      RECT 0.0000 369.0500 678.5000 369.2500 ;
      RECT 0.0000 368.7500 679.2000 369.0500 ;
      RECT 0.7000 368.5500 679.2000 368.7500 ;
      RECT 0.7000 368.4500 678.5000 368.5500 ;
      RECT 0.0000 368.2500 678.5000 368.4500 ;
      RECT 0.0000 367.9500 679.2000 368.2500 ;
      RECT 0.7000 367.7500 679.2000 367.9500 ;
      RECT 0.7000 367.6500 678.5000 367.7500 ;
      RECT 0.0000 367.4500 678.5000 367.6500 ;
      RECT 0.0000 367.1500 679.2000 367.4500 ;
      RECT 0.7000 366.9500 679.2000 367.1500 ;
      RECT 0.7000 366.8500 678.5000 366.9500 ;
      RECT 0.0000 366.6500 678.5000 366.8500 ;
      RECT 0.0000 366.3500 679.2000 366.6500 ;
      RECT 0.7000 366.1500 679.2000 366.3500 ;
      RECT 0.7000 366.0500 678.5000 366.1500 ;
      RECT 0.0000 365.8500 678.5000 366.0500 ;
      RECT 0.0000 365.5500 679.2000 365.8500 ;
      RECT 0.7000 365.3500 679.2000 365.5500 ;
      RECT 0.7000 365.2500 678.5000 365.3500 ;
      RECT 0.0000 365.0500 678.5000 365.2500 ;
      RECT 0.0000 364.7500 679.2000 365.0500 ;
      RECT 0.7000 364.5500 679.2000 364.7500 ;
      RECT 0.7000 364.4500 678.5000 364.5500 ;
      RECT 0.0000 364.2500 678.5000 364.4500 ;
      RECT 0.0000 363.9500 679.2000 364.2500 ;
      RECT 0.7000 363.7500 679.2000 363.9500 ;
      RECT 0.7000 363.6500 678.5000 363.7500 ;
      RECT 0.0000 363.4500 678.5000 363.6500 ;
      RECT 0.0000 363.1500 679.2000 363.4500 ;
      RECT 0.7000 362.9500 679.2000 363.1500 ;
      RECT 0.7000 362.8500 678.5000 362.9500 ;
      RECT 0.0000 362.6500 678.5000 362.8500 ;
      RECT 0.0000 362.3500 679.2000 362.6500 ;
      RECT 0.7000 362.1500 679.2000 362.3500 ;
      RECT 0.7000 362.0500 678.5000 362.1500 ;
      RECT 0.0000 361.8500 678.5000 362.0500 ;
      RECT 0.0000 361.5500 679.2000 361.8500 ;
      RECT 0.7000 361.3500 679.2000 361.5500 ;
      RECT 0.7000 361.2500 678.5000 361.3500 ;
      RECT 0.0000 361.0500 678.5000 361.2500 ;
      RECT 0.0000 360.7500 679.2000 361.0500 ;
      RECT 0.7000 360.5500 679.2000 360.7500 ;
      RECT 0.7000 360.4500 678.5000 360.5500 ;
      RECT 0.0000 360.2500 678.5000 360.4500 ;
      RECT 0.0000 359.9500 679.2000 360.2500 ;
      RECT 0.7000 359.7500 679.2000 359.9500 ;
      RECT 0.7000 359.6500 678.5000 359.7500 ;
      RECT 0.0000 359.4500 678.5000 359.6500 ;
      RECT 0.0000 359.1500 679.2000 359.4500 ;
      RECT 0.7000 358.9500 679.2000 359.1500 ;
      RECT 0.7000 358.8500 678.5000 358.9500 ;
      RECT 0.0000 358.6500 678.5000 358.8500 ;
      RECT 0.0000 358.3500 679.2000 358.6500 ;
      RECT 0.7000 358.1500 679.2000 358.3500 ;
      RECT 0.7000 358.0500 678.5000 358.1500 ;
      RECT 0.0000 357.8500 678.5000 358.0500 ;
      RECT 0.0000 357.5500 679.2000 357.8500 ;
      RECT 0.7000 357.3500 679.2000 357.5500 ;
      RECT 0.7000 357.2500 678.5000 357.3500 ;
      RECT 0.0000 357.0500 678.5000 357.2500 ;
      RECT 0.0000 356.7500 679.2000 357.0500 ;
      RECT 0.7000 356.5500 679.2000 356.7500 ;
      RECT 0.7000 356.4500 678.5000 356.5500 ;
      RECT 0.0000 356.2500 678.5000 356.4500 ;
      RECT 0.0000 355.9500 679.2000 356.2500 ;
      RECT 0.7000 355.7500 679.2000 355.9500 ;
      RECT 0.7000 355.6500 678.5000 355.7500 ;
      RECT 0.0000 355.4500 678.5000 355.6500 ;
      RECT 0.0000 355.1500 679.2000 355.4500 ;
      RECT 0.7000 354.9500 679.2000 355.1500 ;
      RECT 0.7000 354.8500 678.5000 354.9500 ;
      RECT 0.0000 354.6500 678.5000 354.8500 ;
      RECT 0.0000 354.3500 679.2000 354.6500 ;
      RECT 0.7000 354.1500 679.2000 354.3500 ;
      RECT 0.7000 354.0500 678.5000 354.1500 ;
      RECT 0.0000 353.8500 678.5000 354.0500 ;
      RECT 0.0000 353.5500 679.2000 353.8500 ;
      RECT 0.7000 353.3500 679.2000 353.5500 ;
      RECT 0.7000 353.2500 678.5000 353.3500 ;
      RECT 0.0000 353.0500 678.5000 353.2500 ;
      RECT 0.0000 352.7500 679.2000 353.0500 ;
      RECT 0.7000 352.5500 679.2000 352.7500 ;
      RECT 0.7000 352.4500 678.5000 352.5500 ;
      RECT 0.0000 352.2500 678.5000 352.4500 ;
      RECT 0.0000 351.9500 679.2000 352.2500 ;
      RECT 0.7000 351.7500 679.2000 351.9500 ;
      RECT 0.7000 351.6500 678.5000 351.7500 ;
      RECT 0.0000 351.4500 678.5000 351.6500 ;
      RECT 0.0000 351.1500 679.2000 351.4500 ;
      RECT 0.7000 350.9500 679.2000 351.1500 ;
      RECT 0.7000 350.8500 678.5000 350.9500 ;
      RECT 0.0000 350.6500 678.5000 350.8500 ;
      RECT 0.0000 350.3500 679.2000 350.6500 ;
      RECT 0.7000 350.1500 679.2000 350.3500 ;
      RECT 0.7000 350.0500 678.5000 350.1500 ;
      RECT 0.0000 349.8500 678.5000 350.0500 ;
      RECT 0.0000 349.5500 679.2000 349.8500 ;
      RECT 0.7000 349.3500 679.2000 349.5500 ;
      RECT 0.7000 349.2500 678.5000 349.3500 ;
      RECT 0.0000 349.0500 678.5000 349.2500 ;
      RECT 0.0000 348.7500 679.2000 349.0500 ;
      RECT 0.7000 348.5500 679.2000 348.7500 ;
      RECT 0.7000 348.4500 678.5000 348.5500 ;
      RECT 0.0000 348.2500 678.5000 348.4500 ;
      RECT 0.0000 347.9500 679.2000 348.2500 ;
      RECT 0.7000 347.7500 679.2000 347.9500 ;
      RECT 0.7000 347.6500 678.5000 347.7500 ;
      RECT 0.0000 347.4500 678.5000 347.6500 ;
      RECT 0.0000 347.1500 679.2000 347.4500 ;
      RECT 0.7000 346.9500 679.2000 347.1500 ;
      RECT 0.7000 346.8500 678.5000 346.9500 ;
      RECT 0.0000 346.6500 678.5000 346.8500 ;
      RECT 0.0000 346.3500 679.2000 346.6500 ;
      RECT 0.7000 346.1500 679.2000 346.3500 ;
      RECT 0.7000 346.0500 678.5000 346.1500 ;
      RECT 0.0000 345.8500 678.5000 346.0500 ;
      RECT 0.0000 345.5500 679.2000 345.8500 ;
      RECT 0.7000 345.3500 679.2000 345.5500 ;
      RECT 0.7000 345.2500 678.5000 345.3500 ;
      RECT 0.0000 345.0500 678.5000 345.2500 ;
      RECT 0.0000 344.7500 679.2000 345.0500 ;
      RECT 0.7000 344.5500 679.2000 344.7500 ;
      RECT 0.7000 344.4500 678.5000 344.5500 ;
      RECT 0.0000 344.2500 678.5000 344.4500 ;
      RECT 0.0000 343.9500 679.2000 344.2500 ;
      RECT 0.7000 343.7500 679.2000 343.9500 ;
      RECT 0.7000 343.6500 678.5000 343.7500 ;
      RECT 0.0000 343.4500 678.5000 343.6500 ;
      RECT 0.0000 343.1500 679.2000 343.4500 ;
      RECT 0.7000 342.9500 679.2000 343.1500 ;
      RECT 0.7000 342.8500 678.5000 342.9500 ;
      RECT 0.0000 342.6500 678.5000 342.8500 ;
      RECT 0.0000 342.3500 679.2000 342.6500 ;
      RECT 0.7000 342.1500 679.2000 342.3500 ;
      RECT 0.7000 342.0500 678.5000 342.1500 ;
      RECT 0.0000 341.8500 678.5000 342.0500 ;
      RECT 0.0000 341.5500 679.2000 341.8500 ;
      RECT 0.7000 341.3500 679.2000 341.5500 ;
      RECT 0.7000 341.2500 678.5000 341.3500 ;
      RECT 0.0000 341.0500 678.5000 341.2500 ;
      RECT 0.0000 340.7500 679.2000 341.0500 ;
      RECT 0.7000 340.5500 679.2000 340.7500 ;
      RECT 0.7000 340.4500 678.5000 340.5500 ;
      RECT 0.0000 340.2500 678.5000 340.4500 ;
      RECT 0.0000 339.9500 679.2000 340.2500 ;
      RECT 0.7000 339.7500 679.2000 339.9500 ;
      RECT 0.7000 339.6500 678.5000 339.7500 ;
      RECT 0.0000 339.4500 678.5000 339.6500 ;
      RECT 0.0000 339.1500 679.2000 339.4500 ;
      RECT 0.7000 338.9500 679.2000 339.1500 ;
      RECT 0.7000 338.8500 678.5000 338.9500 ;
      RECT 0.0000 338.6500 678.5000 338.8500 ;
      RECT 0.0000 338.3500 679.2000 338.6500 ;
      RECT 0.7000 338.1500 679.2000 338.3500 ;
      RECT 0.7000 338.0500 678.5000 338.1500 ;
      RECT 0.0000 337.8500 678.5000 338.0500 ;
      RECT 0.0000 337.5500 679.2000 337.8500 ;
      RECT 0.7000 337.3500 679.2000 337.5500 ;
      RECT 0.7000 337.2500 678.5000 337.3500 ;
      RECT 0.0000 337.0500 678.5000 337.2500 ;
      RECT 0.0000 336.7500 679.2000 337.0500 ;
      RECT 0.7000 336.5500 679.2000 336.7500 ;
      RECT 0.7000 336.4500 678.5000 336.5500 ;
      RECT 0.0000 336.2500 678.5000 336.4500 ;
      RECT 0.0000 335.9500 679.2000 336.2500 ;
      RECT 0.7000 335.7500 679.2000 335.9500 ;
      RECT 0.7000 335.6500 678.5000 335.7500 ;
      RECT 0.0000 335.4500 678.5000 335.6500 ;
      RECT 0.0000 335.1500 679.2000 335.4500 ;
      RECT 0.7000 334.9500 679.2000 335.1500 ;
      RECT 0.7000 334.8500 678.5000 334.9500 ;
      RECT 0.0000 334.6500 678.5000 334.8500 ;
      RECT 0.0000 334.3500 679.2000 334.6500 ;
      RECT 0.7000 334.1500 679.2000 334.3500 ;
      RECT 0.7000 334.0500 678.5000 334.1500 ;
      RECT 0.0000 333.8500 678.5000 334.0500 ;
      RECT 0.0000 333.5500 679.2000 333.8500 ;
      RECT 0.7000 333.3500 679.2000 333.5500 ;
      RECT 0.7000 333.2500 678.5000 333.3500 ;
      RECT 0.0000 333.0500 678.5000 333.2500 ;
      RECT 0.0000 332.7500 679.2000 333.0500 ;
      RECT 0.7000 332.5500 679.2000 332.7500 ;
      RECT 0.7000 332.4500 678.5000 332.5500 ;
      RECT 0.0000 332.2500 678.5000 332.4500 ;
      RECT 0.0000 331.9500 679.2000 332.2500 ;
      RECT 0.7000 331.7500 679.2000 331.9500 ;
      RECT 0.7000 331.6500 678.5000 331.7500 ;
      RECT 0.0000 331.4500 678.5000 331.6500 ;
      RECT 0.0000 331.1500 679.2000 331.4500 ;
      RECT 0.7000 330.9500 679.2000 331.1500 ;
      RECT 0.7000 330.8500 678.5000 330.9500 ;
      RECT 0.0000 330.6500 678.5000 330.8500 ;
      RECT 0.0000 330.3500 679.2000 330.6500 ;
      RECT 0.7000 330.1500 679.2000 330.3500 ;
      RECT 0.7000 330.0500 678.5000 330.1500 ;
      RECT 0.0000 329.8500 678.5000 330.0500 ;
      RECT 0.0000 329.5500 679.2000 329.8500 ;
      RECT 0.7000 329.3500 679.2000 329.5500 ;
      RECT 0.7000 329.2500 678.5000 329.3500 ;
      RECT 0.0000 329.0500 678.5000 329.2500 ;
      RECT 0.0000 328.7500 679.2000 329.0500 ;
      RECT 0.7000 328.5500 679.2000 328.7500 ;
      RECT 0.7000 328.4500 678.5000 328.5500 ;
      RECT 0.0000 328.2500 678.5000 328.4500 ;
      RECT 0.0000 327.9500 679.2000 328.2500 ;
      RECT 0.7000 327.7500 679.2000 327.9500 ;
      RECT 0.7000 327.6500 678.5000 327.7500 ;
      RECT 0.0000 327.4500 678.5000 327.6500 ;
      RECT 0.0000 327.1500 679.2000 327.4500 ;
      RECT 0.7000 326.9500 679.2000 327.1500 ;
      RECT 0.7000 326.8500 678.5000 326.9500 ;
      RECT 0.0000 326.6500 678.5000 326.8500 ;
      RECT 0.0000 326.3500 679.2000 326.6500 ;
      RECT 0.7000 326.1500 679.2000 326.3500 ;
      RECT 0.7000 326.0500 678.5000 326.1500 ;
      RECT 0.0000 325.8500 678.5000 326.0500 ;
      RECT 0.0000 325.5500 679.2000 325.8500 ;
      RECT 0.7000 325.3500 679.2000 325.5500 ;
      RECT 0.7000 325.2500 678.5000 325.3500 ;
      RECT 0.0000 325.0500 678.5000 325.2500 ;
      RECT 0.0000 324.7500 679.2000 325.0500 ;
      RECT 0.7000 324.5500 679.2000 324.7500 ;
      RECT 0.7000 324.4500 678.5000 324.5500 ;
      RECT 0.0000 324.2500 678.5000 324.4500 ;
      RECT 0.0000 323.9500 679.2000 324.2500 ;
      RECT 0.7000 323.7500 679.2000 323.9500 ;
      RECT 0.7000 323.6500 678.5000 323.7500 ;
      RECT 0.0000 323.4500 678.5000 323.6500 ;
      RECT 0.0000 323.1500 679.2000 323.4500 ;
      RECT 0.7000 322.9500 679.2000 323.1500 ;
      RECT 0.7000 322.8500 678.5000 322.9500 ;
      RECT 0.0000 322.6500 678.5000 322.8500 ;
      RECT 0.0000 322.3500 679.2000 322.6500 ;
      RECT 0.7000 322.1500 679.2000 322.3500 ;
      RECT 0.7000 322.0500 678.5000 322.1500 ;
      RECT 0.0000 321.8500 678.5000 322.0500 ;
      RECT 0.0000 321.5500 679.2000 321.8500 ;
      RECT 0.7000 321.3500 679.2000 321.5500 ;
      RECT 0.7000 321.2500 678.5000 321.3500 ;
      RECT 0.0000 321.0500 678.5000 321.2500 ;
      RECT 0.0000 320.7500 679.2000 321.0500 ;
      RECT 0.7000 320.5500 679.2000 320.7500 ;
      RECT 0.7000 320.4500 678.5000 320.5500 ;
      RECT 0.0000 320.2500 678.5000 320.4500 ;
      RECT 0.0000 319.9500 679.2000 320.2500 ;
      RECT 0.7000 319.7500 679.2000 319.9500 ;
      RECT 0.7000 319.6500 678.5000 319.7500 ;
      RECT 0.0000 319.4500 678.5000 319.6500 ;
      RECT 0.0000 319.1500 679.2000 319.4500 ;
      RECT 0.7000 318.9500 679.2000 319.1500 ;
      RECT 0.7000 318.8500 678.5000 318.9500 ;
      RECT 0.0000 318.6500 678.5000 318.8500 ;
      RECT 0.0000 318.3500 679.2000 318.6500 ;
      RECT 0.7000 318.1500 679.2000 318.3500 ;
      RECT 0.7000 318.0500 678.5000 318.1500 ;
      RECT 0.0000 317.8500 678.5000 318.0500 ;
      RECT 0.0000 317.5500 679.2000 317.8500 ;
      RECT 0.7000 317.3500 679.2000 317.5500 ;
      RECT 0.7000 317.2500 678.5000 317.3500 ;
      RECT 0.0000 317.0500 678.5000 317.2500 ;
      RECT 0.0000 316.7500 679.2000 317.0500 ;
      RECT 0.7000 316.5500 679.2000 316.7500 ;
      RECT 0.7000 316.4500 678.5000 316.5500 ;
      RECT 0.0000 316.2500 678.5000 316.4500 ;
      RECT 0.0000 315.9500 679.2000 316.2500 ;
      RECT 0.7000 315.7500 679.2000 315.9500 ;
      RECT 0.7000 315.6500 678.5000 315.7500 ;
      RECT 0.0000 315.4500 678.5000 315.6500 ;
      RECT 0.0000 315.1500 679.2000 315.4500 ;
      RECT 0.7000 314.9500 679.2000 315.1500 ;
      RECT 0.7000 314.8500 678.5000 314.9500 ;
      RECT 0.0000 314.6500 678.5000 314.8500 ;
      RECT 0.0000 314.3500 679.2000 314.6500 ;
      RECT 0.7000 314.1500 679.2000 314.3500 ;
      RECT 0.7000 314.0500 678.5000 314.1500 ;
      RECT 0.0000 313.8500 678.5000 314.0500 ;
      RECT 0.0000 313.5500 679.2000 313.8500 ;
      RECT 0.7000 313.3500 679.2000 313.5500 ;
      RECT 0.7000 313.2500 678.5000 313.3500 ;
      RECT 0.0000 313.0500 678.5000 313.2500 ;
      RECT 0.0000 312.7500 679.2000 313.0500 ;
      RECT 0.7000 312.5500 679.2000 312.7500 ;
      RECT 0.7000 312.4500 678.5000 312.5500 ;
      RECT 0.0000 312.2500 678.5000 312.4500 ;
      RECT 0.0000 311.9500 679.2000 312.2500 ;
      RECT 0.7000 311.7500 679.2000 311.9500 ;
      RECT 0.7000 311.6500 678.5000 311.7500 ;
      RECT 0.0000 311.4500 678.5000 311.6500 ;
      RECT 0.0000 311.1500 679.2000 311.4500 ;
      RECT 0.7000 310.9500 679.2000 311.1500 ;
      RECT 0.7000 310.8500 678.5000 310.9500 ;
      RECT 0.0000 310.6500 678.5000 310.8500 ;
      RECT 0.0000 310.3500 679.2000 310.6500 ;
      RECT 0.7000 310.1500 679.2000 310.3500 ;
      RECT 0.7000 310.0500 678.5000 310.1500 ;
      RECT 0.0000 309.8500 678.5000 310.0500 ;
      RECT 0.0000 309.5500 679.2000 309.8500 ;
      RECT 0.7000 309.3500 679.2000 309.5500 ;
      RECT 0.7000 309.2500 678.5000 309.3500 ;
      RECT 0.0000 309.0500 678.5000 309.2500 ;
      RECT 0.0000 308.7500 679.2000 309.0500 ;
      RECT 0.7000 308.5500 679.2000 308.7500 ;
      RECT 0.7000 308.4500 678.5000 308.5500 ;
      RECT 0.0000 308.2500 678.5000 308.4500 ;
      RECT 0.0000 307.9500 679.2000 308.2500 ;
      RECT 0.7000 307.7500 679.2000 307.9500 ;
      RECT 0.7000 307.6500 678.5000 307.7500 ;
      RECT 0.0000 307.4500 678.5000 307.6500 ;
      RECT 0.0000 307.1500 679.2000 307.4500 ;
      RECT 0.7000 306.9500 679.2000 307.1500 ;
      RECT 0.7000 306.8500 678.5000 306.9500 ;
      RECT 0.0000 306.6500 678.5000 306.8500 ;
      RECT 0.0000 306.3500 679.2000 306.6500 ;
      RECT 0.7000 306.1500 679.2000 306.3500 ;
      RECT 0.7000 306.0500 678.5000 306.1500 ;
      RECT 0.0000 305.8500 678.5000 306.0500 ;
      RECT 0.0000 305.5500 679.2000 305.8500 ;
      RECT 0.7000 305.3500 679.2000 305.5500 ;
      RECT 0.7000 305.2500 678.5000 305.3500 ;
      RECT 0.0000 305.0500 678.5000 305.2500 ;
      RECT 0.0000 304.7500 679.2000 305.0500 ;
      RECT 0.7000 304.5500 679.2000 304.7500 ;
      RECT 0.7000 304.4500 678.5000 304.5500 ;
      RECT 0.0000 304.2500 678.5000 304.4500 ;
      RECT 0.0000 303.7500 679.2000 304.2500 ;
      RECT 0.0000 303.4500 678.5000 303.7500 ;
      RECT 0.0000 302.9500 679.2000 303.4500 ;
      RECT 0.0000 302.6500 678.5000 302.9500 ;
      RECT 0.0000 302.1500 679.2000 302.6500 ;
      RECT 0.0000 301.8500 678.5000 302.1500 ;
      RECT 0.0000 301.3500 679.2000 301.8500 ;
      RECT 0.0000 301.0500 678.5000 301.3500 ;
      RECT 0.0000 300.5500 679.2000 301.0500 ;
      RECT 0.0000 300.2500 678.5000 300.5500 ;
      RECT 0.0000 299.7500 679.2000 300.2500 ;
      RECT 0.0000 299.4500 678.5000 299.7500 ;
      RECT 0.0000 298.9500 679.2000 299.4500 ;
      RECT 0.0000 298.6500 678.5000 298.9500 ;
      RECT 0.0000 298.1500 679.2000 298.6500 ;
      RECT 0.0000 297.8500 678.5000 298.1500 ;
      RECT 0.0000 297.3500 679.2000 297.8500 ;
      RECT 0.0000 297.0500 678.5000 297.3500 ;
      RECT 0.0000 296.5500 679.2000 297.0500 ;
      RECT 0.0000 296.2500 678.5000 296.5500 ;
      RECT 0.0000 295.7500 679.2000 296.2500 ;
      RECT 0.0000 295.4500 678.5000 295.7500 ;
      RECT 0.0000 294.9500 679.2000 295.4500 ;
      RECT 0.0000 294.6500 678.5000 294.9500 ;
      RECT 0.0000 294.1500 679.2000 294.6500 ;
      RECT 0.0000 293.8500 678.5000 294.1500 ;
      RECT 0.0000 293.3500 679.2000 293.8500 ;
      RECT 0.0000 293.0500 678.5000 293.3500 ;
      RECT 0.0000 292.5500 679.2000 293.0500 ;
      RECT 0.0000 292.2500 678.5000 292.5500 ;
      RECT 0.0000 291.7500 679.2000 292.2500 ;
      RECT 0.0000 291.4500 678.5000 291.7500 ;
      RECT 0.0000 290.9500 679.2000 291.4500 ;
      RECT 0.0000 290.6500 678.5000 290.9500 ;
      RECT 0.0000 290.1500 679.2000 290.6500 ;
      RECT 0.0000 289.8500 678.5000 290.1500 ;
      RECT 0.0000 289.3500 679.2000 289.8500 ;
      RECT 0.0000 289.0500 678.5000 289.3500 ;
      RECT 0.0000 288.5500 679.2000 289.0500 ;
      RECT 0.0000 288.2500 678.5000 288.5500 ;
      RECT 0.0000 287.7500 679.2000 288.2500 ;
      RECT 0.0000 287.4500 678.5000 287.7500 ;
      RECT 0.0000 286.9500 679.2000 287.4500 ;
      RECT 0.0000 286.6500 678.5000 286.9500 ;
      RECT 0.0000 286.1500 679.2000 286.6500 ;
      RECT 0.0000 285.8500 678.5000 286.1500 ;
      RECT 0.0000 285.3500 679.2000 285.8500 ;
      RECT 0.0000 285.0500 678.5000 285.3500 ;
      RECT 0.0000 284.5500 679.2000 285.0500 ;
      RECT 0.0000 284.2500 678.5000 284.5500 ;
      RECT 0.0000 283.7500 679.2000 284.2500 ;
      RECT 0.0000 283.4500 678.5000 283.7500 ;
      RECT 0.0000 282.9500 679.2000 283.4500 ;
      RECT 0.0000 282.6500 678.5000 282.9500 ;
      RECT 0.0000 282.1500 679.2000 282.6500 ;
      RECT 0.0000 281.8500 678.5000 282.1500 ;
      RECT 0.0000 281.3500 679.2000 281.8500 ;
      RECT 0.0000 281.0500 678.5000 281.3500 ;
      RECT 0.0000 280.5500 679.2000 281.0500 ;
      RECT 0.0000 280.2500 678.5000 280.5500 ;
      RECT 0.0000 279.7500 679.2000 280.2500 ;
      RECT 0.0000 279.4500 678.5000 279.7500 ;
      RECT 0.0000 278.9500 679.2000 279.4500 ;
      RECT 0.0000 278.6500 678.5000 278.9500 ;
      RECT 0.0000 278.1500 679.2000 278.6500 ;
      RECT 0.0000 277.8500 678.5000 278.1500 ;
      RECT 0.0000 277.3500 679.2000 277.8500 ;
      RECT 0.0000 277.0500 678.5000 277.3500 ;
      RECT 0.0000 276.5500 679.2000 277.0500 ;
      RECT 0.0000 276.2500 678.5000 276.5500 ;
      RECT 0.0000 275.7500 679.2000 276.2500 ;
      RECT 0.0000 275.4500 678.5000 275.7500 ;
      RECT 0.0000 274.9500 679.2000 275.4500 ;
      RECT 0.0000 274.6500 678.5000 274.9500 ;
      RECT 0.0000 274.1500 679.2000 274.6500 ;
      RECT 0.0000 273.8500 678.5000 274.1500 ;
      RECT 0.0000 273.3500 679.2000 273.8500 ;
      RECT 0.0000 273.0500 678.5000 273.3500 ;
      RECT 0.0000 272.5500 679.2000 273.0500 ;
      RECT 0.0000 272.2500 678.5000 272.5500 ;
      RECT 0.0000 271.7500 679.2000 272.2500 ;
      RECT 0.0000 271.4500 678.5000 271.7500 ;
      RECT 0.0000 270.9500 679.2000 271.4500 ;
      RECT 0.0000 270.6500 678.5000 270.9500 ;
      RECT 0.0000 270.1500 679.2000 270.6500 ;
      RECT 0.0000 269.8500 678.5000 270.1500 ;
      RECT 0.0000 269.3500 679.2000 269.8500 ;
      RECT 0.0000 269.0500 678.5000 269.3500 ;
      RECT 0.0000 268.5500 679.2000 269.0500 ;
      RECT 0.0000 268.2500 678.5000 268.5500 ;
      RECT 0.0000 267.7500 679.2000 268.2500 ;
      RECT 0.0000 267.4500 678.5000 267.7500 ;
      RECT 0.0000 266.9500 679.2000 267.4500 ;
      RECT 0.0000 266.6500 678.5000 266.9500 ;
      RECT 0.0000 266.1500 679.2000 266.6500 ;
      RECT 0.0000 265.8500 678.5000 266.1500 ;
      RECT 0.0000 265.3500 679.2000 265.8500 ;
      RECT 0.0000 265.0500 678.5000 265.3500 ;
      RECT 0.0000 0.0000 679.2000 265.0500 ;
    LAYER M4 ;
      RECT 339.8500 676.3800 679.2000 677.0000 ;
      RECT 0.0000 676.3800 339.5500 677.0000 ;
      RECT 0.0000 0.6200 679.2000 676.3800 ;
      RECT 339.8500 0.0000 679.2000 0.6200 ;
      RECT 0.0000 0.0000 339.5500 0.6200 ;
    LAYER M5 ;
      RECT 0.0000 408.7500 679.2000 677.0000 ;
      RECT 0.0000 408.4500 678.5800 408.7500 ;
      RECT 0.0000 401.5500 679.2000 408.4500 ;
      RECT 0.0000 401.2500 678.5800 401.5500 ;
      RECT 0.0000 397.1500 679.2000 401.2500 ;
      RECT 0.0000 396.8500 678.5800 397.1500 ;
      RECT 0.0000 394.3500 679.2000 396.8500 ;
      RECT 0.0000 394.0500 678.5800 394.3500 ;
      RECT 0.0000 383.9500 679.2000 394.0500 ;
      RECT 0.0000 383.6500 678.5800 383.9500 ;
      RECT 0.0000 349.5500 679.2000 383.6500 ;
      RECT 0.0000 349.2500 678.5800 349.5500 ;
      RECT 0.0000 339.9500 679.2000 349.2500 ;
      RECT 0.0000 339.6500 678.5800 339.9500 ;
      RECT 0.0000 0.0000 679.2000 339.6500 ;
    LAYER M6 ;
      RECT 339.8500 676.3800 679.2000 677.0000 ;
      RECT 0.0000 676.3800 339.5500 677.0000 ;
      RECT 0.0000 0.6200 679.2000 676.3800 ;
      RECT 339.8500 0.0000 679.2000 0.6200 ;
      RECT 0.0000 0.0000 339.5500 0.6200 ;
    LAYER M7 ;
      RECT 0.0000 0.0000 679.2000 677.0000 ;
    LAYER M8 ;
      RECT 340.3000 675.1850 679.2000 677.0000 ;
      RECT 0.0000 675.1850 339.1000 677.0000 ;
      RECT 0.0000 0.0000 679.2000 675.1850 ;
  END
END core

END LIBRARY
